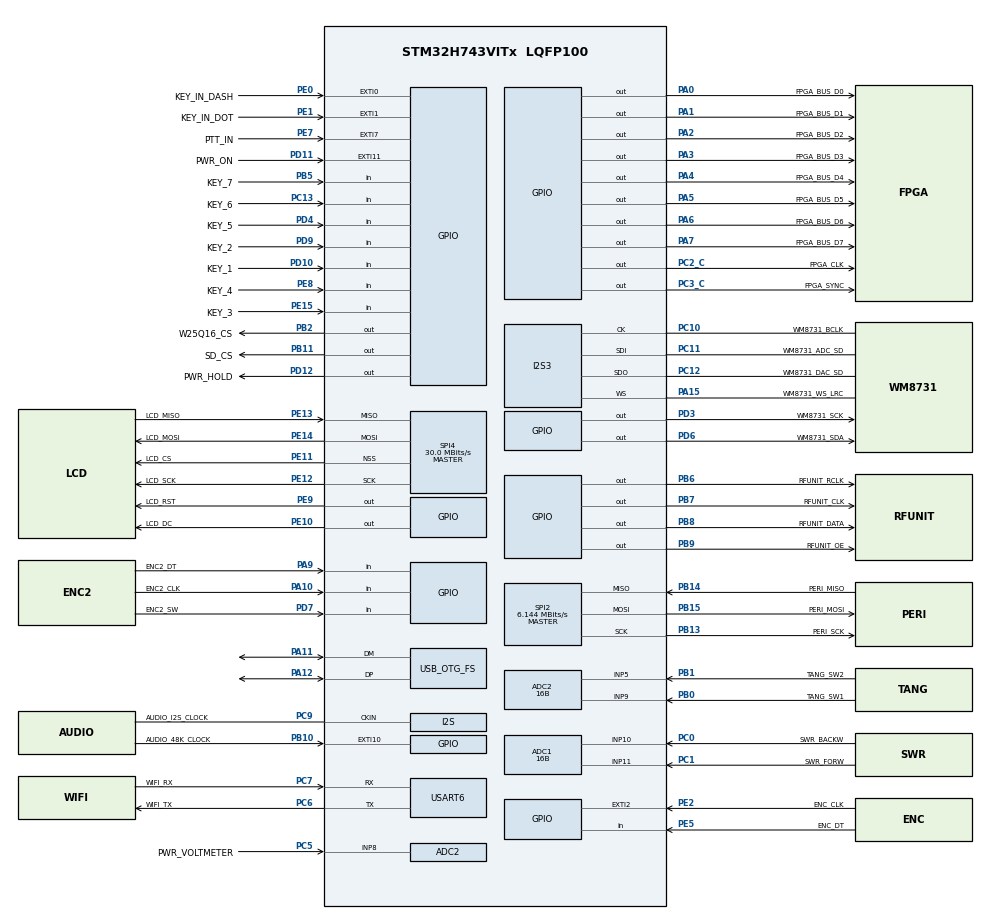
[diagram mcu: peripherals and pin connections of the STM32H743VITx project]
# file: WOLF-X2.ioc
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ADC1.ClockPrescaler=ADC_CLOCK_ASYNC_DIV256
ADC1.ContinuousConvMode=ENABLE
ADC1.ConversionDataManagement=ADC_CONVERSIONDATA_DR
ADC1.EOCSelection=ADC_EOC_SEQ_CONV
ADC1.EnableInjectedConversion=ENABLE
ADC1.EnableInjectedOversampling=DISABLE
ADC1.EnableRegularConversion=DISABLE
ADC1.ExternalTrigInjecConv=ADC_EXTERNALTRIGINJEC_T4_TRGO
ADC1.InjNumberOfConversion=2
ADC1.InjectedChannel-1\#ChannelInjectedConversion=ADC_CHANNEL_11
ADC1.InjectedChannel-2\#ChannelInjectedConversion=ADC_CHANNEL_10
ADC1.InjectedConvMode=None
ADC1.InjectedOffsetNumber-1\#ChannelInjectedConversion=ADC_OFFSET_NONE
ADC1.InjectedOffsetNumber-2\#ChannelInjectedConversion=ADC_OFFSET_NONE
ADC1.InjectedRank-1\#ChannelInjectedConversion=1
ADC1.InjectedRank-2\#ChannelInjectedConversion=2
ADC1.InjectedSamplingTime-1\#ChannelInjectedConversion=ADC_SAMPLETIME_1CYCLE_5
ADC1.InjectedSamplingTime-2\#ChannelInjectedConversion=ADC_SAMPLETIME_1CYCLE_5
ADC1.LowPowerAutoWait=DISABLE
ADC1.Overrun=ADC_OVR_DATA_OVERWRITTEN
ADC1.Resolution=ADC_RESOLUTION_16B
ADC1.injectedQueueMode=DISABLE
ADC1.master=1
ADC2.ClockPrescaler=ADC_CLOCK_ASYNC_DIV256
ADC2.ContinuousConvMode=ENABLE
ADC2.EOCSelection=ADC_EOC_SEQ_CONV
ADC2.EnableInjectedConversion=ENABLE
ADC2.EnableInjectedOversampling=DISABLE
ADC2.EnableRegularConversion=DISABLE
ADC2.ExternalTrigInjecConv=ADC_EXTERNALTRIGINJEC_T4_TRGO
ADC2.InjNumberOfConversion=4
ADC2.InjectedChannel-2\#ChannelInjectedConversion=ADC_CHANNEL_9
ADC2.InjectedChannel-3\#ChannelInjectedConversion=ADC_CHANNEL_5
ADC2.InjectedChannel-4\#ChannelInjectedConversion=ADC_CHANNEL_8
ADC2.InjectedChannel-5\#ChannelInjectedConversion=ADC_CHANNEL_5
ADC2.InjectedConvMode=None
ADC2.InjectedOffsetNumber-2\#ChannelInjectedConversion=ADC_OFFSET_NONE
ADC2.InjectedOffsetNumber-3\#ChannelInjectedConversion=ADC_OFFSET_NONE
ADC2.InjectedOffsetNumber-4\#ChannelInjectedConversion=ADC_OFFSET_NONE
ADC2.InjectedOffsetNumber-5\#ChannelInjectedConversion=ADC_OFFSET_NONE
ADC2.InjectedRank-2\#ChannelInjectedConversion=1
ADC2.InjectedRank-3\#ChannelInjectedConversion=2
ADC2.InjectedRank-4\#ChannelInjectedConversion=3
ADC2.InjectedRank-5\#ChannelInjectedConversion=4
ADC2.InjectedSamplingTime-2\#ChannelInjectedConversion=ADC_SAMPLETIME_32CYCLES_5
ADC2.InjectedSamplingTime-3\#ChannelInjectedConversion=ADC_SAMPLETIME_32CYCLES_5
ADC2.InjectedSamplingTime-4\#ChannelInjectedConversion=ADC_SAMPLETIME_32CYCLES_5
ADC2.InjectedSamplingTime-5\#ChannelInjectedConversion=ADC_SAMPLETIME_1CYCLE_5
ADC2.LowPowerAutoWait=DISABLE
ADC2.Overrun=ADC_OVR_DATA_OVERWRITTEN
ADC2.Resolution=ADC_RESOLUTION_16B
ADC3.ClockPrescaler=ADC_CLOCK_ASYNC_DIV256
ADC3.ContinuousConvMode=ENABLE
ADC3.EOCSelection=ADC_EOC_SEQ_CONV
ADC3.EnableInjectedConversion=ENABLE
ADC3.EnableInjectedOversampling=DISABLE
ADC3.EnableRegularConversion=DISABLE
ADC3.ExternalTrigInjecConv=ADC_EXTERNALTRIGINJEC_T4_TRGO
ADC3.InjNumberOfConversion=3
ADC3.InjectedChannel-2\#ChannelInjectedConversion=ADC_CHANNEL_TEMPSENSOR
ADC3.InjectedChannel-4\#ChannelInjectedConversion=ADC_CHANNEL_VREFINT
ADC3.InjectedChannel-5\#ChannelInjectedConversion=ADC_CHANNEL_VBAT
ADC3.InjectedConvMode=None
ADC3.InjectedOffsetNumber-2\#ChannelInjectedConversion=ADC_OFFSET_NONE
ADC3.InjectedOffsetNumber-4\#ChannelInjectedConversion=ADC_OFFSET_NONE
ADC3.InjectedOffsetNumber-5\#ChannelInjectedConversion=ADC_OFFSET_NONE
ADC3.InjectedRank-2\#ChannelInjectedConversion=1
ADC3.InjectedRank-4\#ChannelInjectedConversion=2
ADC3.InjectedRank-5\#ChannelInjectedConversion=3
ADC3.InjectedSamplingTime-2\#ChannelInjectedConversion=ADC_SAMPLETIME_810CYCLES_5
ADC3.InjectedSamplingTime-4\#ChannelInjectedConversion=ADC_SAMPLETIME_810CYCLES_5
ADC3.InjectedSamplingTime-5\#ChannelInjectedConversion=ADC_SAMPLETIME_810CYCLES_5
ADC3.LowPowerAutoWait=DISABLE
ADC3.Overrun=ADC_OVR_DATA_OVERWRITTEN
ADC3.injectedQueueMode=DISABLE
CORTEX_M7.AccessPermission-Cortex_Memory_Protection_Unit_Region0_Settings=MPU_REGION_FULL_ACCESS
CORTEX_M7.AccessPermission-Cortex_Memory_Protection_Unit_Region2_Settings=MPU_REGION_FULL_ACCESS
CORTEX_M7.BaseAddress-Cortex_Memory_Protection_Unit_Region0_Settings=0x60000000
CORTEX_M7.BaseAddress-Cortex_Memory_Protection_Unit_Region2_Settings=0x38800000
CORTEX_M7.CPU_DCache=Enabled
CORTEX_M7.CPU_ICache=Enabled
CORTEX_M7.DisableExec-Cortex_Memory_Protection_Unit_Region0_Settings=MPU_INSTRUCTION_ACCESS_ENABLE
CORTEX_M7.Enable-Cortex_Memory_Protection_Unit_Region0_Settings=MPU_REGION_ENABLE
CORTEX_M7.Enable-Cortex_Memory_Protection_Unit_Region2_Settings=MPU_REGION_ENABLE
CORTEX_M7.IsShareable-Cortex_Memory_Protection_Unit_Region0_Settings=MPU_ACCESS_SHAREABLE
CORTEX_M7.IsShareable-Cortex_Memory_Protection_Unit_Region2_Settings=MPU_ACCESS_SHAREABLE
CORTEX_M7.MPU_Control=MPU_PRIVILEGED_DEFAULT
CORTEX_M7.Size-Cortex_Memory_Protection_Unit_Region0_Settings=MPU_REGION_SIZE_1MB
CORTEX_M7.Size-Cortex_Memory_Protection_Unit_Region2_Settings=MPU_REGION_SIZE_4KB
CORTEX_M7.TypeExtField-Cortex_Memory_Protection_Unit_Region0_Settings=MPU_TEX_LEVEL0
Dma.Request0=SPI2_RX
Dma.Request1=SPI2_TX
Dma.Request2=SPI4_TX
Dma.Request3=USART6_RX
Dma.SPI2_RX.0.Direction=DMA_PERIPH_TO_MEMORY
Dma.SPI2_RX.0.EventEnable=DISABLE
Dma.SPI2_RX.0.FIFOMode=DMA_FIFOMODE_DISABLE
Dma.SPI2_RX.0.Instance=DMA1_Stream2
Dma.SPI2_RX.0.MemDataAlignment=DMA_MDATAALIGN_BYTE
Dma.SPI2_RX.0.MemInc=DMA_MINC_ENABLE
Dma.SPI2_RX.0.Mode=DMA_NORMAL
Dma.SPI2_RX.0.PeriphDataAlignment=DMA_PDATAALIGN_BYTE
Dma.SPI2_RX.0.PeriphInc=DMA_PINC_DISABLE
Dma.SPI2_RX.0.Polarity=HAL_DMAMUX_REQ_GEN_RISING
Dma.SPI2_RX.0.Priority=DMA_PRIORITY_MEDIUM
Dma.SPI2_RX.0.RequestNumber=1
Dma.SPI2_RX.0.SignalID=NONE
Dma.SPI2_RX.0.SyncEnable=DISABLE
Dma.SPI2_RX.0.SyncPolarity=HAL_DMAMUX_SYNC_NO_EVENT
Dma.SPI2_RX.0.SyncRequestNumber=1
Dma.SPI2_RX.0.SyncSignalID=NONE
Dma.SPI2_TX.1.Direction=DMA_MEMORY_TO_PERIPH
Dma.SPI2_TX.1.EventEnable=DISABLE
Dma.SPI2_TX.1.FIFOMode=DMA_FIFOMODE_DISABLE
Dma.SPI2_TX.1.Instance=DMA1_Stream3
Dma.SPI2_TX.1.MemDataAlignment=DMA_MDATAALIGN_BYTE
Dma.SPI2_TX.1.MemInc=DMA_MINC_ENABLE
Dma.SPI2_TX.1.Mode=DMA_NORMAL
Dma.SPI2_TX.1.PeriphDataAlignment=DMA_PDATAALIGN_BYTE
Dma.SPI2_TX.1.PeriphInc=DMA_PINC_DISABLE
Dma.SPI2_TX.1.Polarity=HAL_DMAMUX_REQ_GEN_RISING
Dma.SPI2_TX.1.Priority=DMA_PRIORITY_MEDIUM
Dma.SPI2_TX.1.RequestNumber=1
Dma.SPI2_TX.1.SignalID=NONE
Dma.SPI2_TX.1.SyncEnable=DISABLE
Dma.SPI2_TX.1.SyncPolarity=HAL_DMAMUX_SYNC_NO_EVENT
Dma.SPI2_TX.1.SyncRequestNumber=1
Dma.SPI2_TX.1.SyncSignalID=NONE
Dma.SPI4_TX.2.Direction=DMA_MEMORY_TO_PERIPH
Dma.SPI4_TX.2.EventEnable=DISABLE
Dma.SPI4_TX.2.FIFOMode=DMA_FIFOMODE_DISABLE
Dma.SPI4_TX.2.Instance=DMA2_Stream5
Dma.SPI4_TX.2.MemDataAlignment=DMA_MDATAALIGN_HALFWORD
Dma.SPI4_TX.2.MemInc=DMA_MINC_ENABLE
Dma.SPI4_TX.2.Mode=DMA_NORMAL
Dma.SPI4_TX.2.PeriphDataAlignment=DMA_PDATAALIGN_HALFWORD
Dma.SPI4_TX.2.PeriphInc=DMA_PINC_DISABLE
Dma.SPI4_TX.2.Polarity=HAL_DMAMUX_REQ_GEN_RISING
Dma.SPI4_TX.2.Priority=DMA_PRIORITY_LOW
Dma.SPI4_TX.2.RequestNumber=1
Dma.SPI4_TX.2.SignalID=NONE
Dma.SPI4_TX.2.SyncEnable=DISABLE
Dma.SPI4_TX.2.SyncPolarity=HAL_DMAMUX_SYNC_NO_EVENT
Dma.SPI4_TX.2.SyncRequestNumber=1
Dma.SPI4_TX.2.SyncSignalID=NONE
Dma.USART6_RX.3.Direction=DMA_PERIPH_TO_MEMORY
Dma.USART6_RX.3.EventEnable=DISABLE
Dma.USART6_RX.3.FIFOMode=DMA_FIFOMODE_DISABLE
Dma.USART6_RX.3.Instance=DMA1_Stream1
Dma.USART6_RX.3.MemDataAlignment=DMA_MDATAALIGN_BYTE
Dma.USART6_RX.3.MemInc=DMA_MINC_ENABLE
Dma.USART6_RX.3.Mode=DMA_CIRCULAR
Dma.USART6_RX.3.PeriphDataAlignment=DMA_PDATAALIGN_BYTE
Dma.USART6_RX.3.PeriphInc=DMA_PINC_DISABLE
Dma.USART6_RX.3.Polarity=HAL_DMAMUX_REQ_GEN_RISING
Dma.USART6_RX.3.Priority=DMA_PRIORITY_HIGH
Dma.USART6_RX.3.RequestNumber=1
Dma.USART6_RX.3.SignalID=NONE
Dma.USART6_RX.3.SyncEnable=DISABLE
Dma.USART6_RX.3.SyncPolarity=HAL_DMAMUX_SYNC_NO_EVENT
Dma.USART6_RX.3.SyncRequestNumber=1
Dma.USART6_RX.3.SyncSignalID=NONE
FATFS._MAX_SS=4096
FATFS._USE_FASTSEEK=0
FATFS._USE_LFN=1
FATFS._USE_MKFS=1
I2S3.AudioFreq=I2S_AUDIOFREQ_48K
I2S3.DataFormat=I2S_DATAFORMAT_32B
I2S3.ErrorAudioFreq=0.0 %
I2S3.FullDuplexMode=I2S_MODE_MASTER_FD
I2S3.Instance=SPI$Index
I2S3.MasterKeepIOState=I2S_MASTER_KEEP_IO_STATE_ENABLE
I2S3.RealAudioFreq=48.0 KHz
I2S3.VirtualMode=I2S_MODE_MASTER
IWDG1.Reload=1500
IWDG1.Window=1500
Mcu.Family=STM32H7
Mcu.Name=STM32H743VITx
Mcu.Package=LQFP100
Mdma.MDMA_Channel0.Request0=SW
Mdma.MDMA_Channel0.RequestsNb=1
Mdma.MDMA_Channel0.SW.0.BlockCount=0
Mdma.MDMA_Channel0.SW.0.BlockDataLength=0
Mdma.MDMA_Channel0.SW.0.BufferTransferLength=32
Mdma.MDMA_Channel0.SW.0.CircularMode=MDMA_LINEAR_LIST
Mdma.MDMA_Channel0.SW.0.DataAlignment=MDMA_DATAALIGN_PACKENABLE
Mdma.MDMA_Channel0.SW.0.DestBlockAddressOffset=0
Mdma.MDMA_Channel0.SW.0.DestBurst=MDMA_DEST_BURST_SINGLE
Mdma.MDMA_Channel0.SW.0.DestDataSize=MDMA_DEST_DATASIZE_WORD
Mdma.MDMA_Channel0.SW.0.DestinationInc=MDMA_DEST_INC_WORD
Mdma.MDMA_Channel0.SW.0.DstAddress=0
Mdma.MDMA_Channel0.SW.0.Endianness=MDMA_LITTLE_ENDIANNESS_PRESERVE
Mdma.MDMA_Channel0.SW.0.Instance=MDMA_Channel0
Mdma.MDMA_Channel0.SW.0.MaskAddress=0
Mdma.MDMA_Channel0.SW.0.MaskData=0
Mdma.MDMA_Channel0.SW.0.Priority=MDMA_PRIORITY_MEDIUM
Mdma.MDMA_Channel0.SW.0.Rank=First
Mdma.MDMA_Channel0.SW.0.SourceBlockAddressOffset=0
Mdma.MDMA_Channel0.SW.0.SourceBurst=MDMA_SOURCE_BURST_SINGLE
Mdma.MDMA_Channel0.SW.0.SourceDataSize=MDMA_SRC_DATASIZE_WORD
Mdma.MDMA_Channel0.SW.0.SourceInc=MDMA_SRC_INC_WORD
Mdma.MDMA_Channel0.SW.0.SrcAddress=0
Mdma.MDMA_Channel0.SW.0.TransferTriggerMode=MDMA_FULL_TRANSFER
Mdma.MDMA_Channel1.Request0=SW
Mdma.MDMA_Channel1.RequestsNb=1
Mdma.MDMA_Channel1.SW.0.BlockCount=0
Mdma.MDMA_Channel1.SW.0.BlockDataLength=0
Mdma.MDMA_Channel1.SW.0.BufferTransferLength=32
Mdma.MDMA_Channel1.SW.0.CircularMode=MDMA_LINEAR_LIST
Mdma.MDMA_Channel1.SW.0.DataAlignment=MDMA_DATAALIGN_PACKENABLE
Mdma.MDMA_Channel1.SW.0.DestBlockAddressOffset=0
Mdma.MDMA_Channel1.SW.0.DestBurst=MDMA_DEST_BURST_SINGLE
Mdma.MDMA_Channel1.SW.0.DestDataSize=MDMA_DEST_DATASIZE_WORD
Mdma.MDMA_Channel1.SW.0.DestinationInc=MDMA_DEST_INC_WORD
Mdma.MDMA_Channel1.SW.0.DstAddress=0
Mdma.MDMA_Channel1.SW.0.Endianness=MDMA_LITTLE_ENDIANNESS_PRESERVE
Mdma.MDMA_Channel1.SW.0.Instance=MDMA_Channel1
Mdma.MDMA_Channel1.SW.0.MaskAddress=0
Mdma.MDMA_Channel1.SW.0.MaskData=0
Mdma.MDMA_Channel1.SW.0.Priority=MDMA_PRIORITY_MEDIUM
Mdma.MDMA_Channel1.SW.0.Rank=First
Mdma.MDMA_Channel1.SW.0.SourceBlockAddressOffset=0
Mdma.MDMA_Channel1.SW.0.SourceBurst=MDMA_SOURCE_BURST_SINGLE
Mdma.MDMA_Channel1.SW.0.SourceDataSize=MDMA_SRC_DATASIZE_WORD
Mdma.MDMA_Channel1.SW.0.SourceInc=MDMA_SRC_INC_WORD
Mdma.MDMA_Channel1.SW.0.SrcAddress=0
Mdma.MDMA_Channel1.SW.0.TransferTriggerMode=MDMA_FULL_TRANSFER
Mdma.MDMA_Channel2.Request0=SW
Mdma.MDMA_Channel2.RequestsNb=1
Mdma.MDMA_Channel2.SW.0.BlockCount=0
Mdma.MDMA_Channel2.SW.0.BlockDataLength=0
Mdma.MDMA_Channel2.SW.0.BufferTransferLength=32
Mdma.MDMA_Channel2.SW.0.CircularMode=MDMA_LINEAR_LIST
Mdma.MDMA_Channel2.SW.0.DataAlignment=MDMA_DATAALIGN_PACKENABLE
Mdma.MDMA_Channel2.SW.0.DestBlockAddressOffset=0
Mdma.MDMA_Channel2.SW.0.DestBurst=MDMA_DEST_BURST_SINGLE
Mdma.MDMA_Channel2.SW.0.DestDataSize=MDMA_DEST_DATASIZE_WORD
Mdma.MDMA_Channel2.SW.0.DestinationInc=MDMA_DEST_INC_WORD
Mdma.MDMA_Channel2.SW.0.DstAddress=0
Mdma.MDMA_Channel2.SW.0.Endianness=MDMA_LITTLE_ENDIANNESS_PRESERVE
Mdma.MDMA_Channel2.SW.0.Instance=MDMA_Channel2
Mdma.MDMA_Channel2.SW.0.MaskAddress=0
Mdma.MDMA_Channel2.SW.0.MaskData=0
Mdma.MDMA_Channel2.SW.0.Priority=MDMA_PRIORITY_MEDIUM
Mdma.MDMA_Channel2.SW.0.Rank=First
Mdma.MDMA_Channel2.SW.0.SourceBlockAddressOffset=0
Mdma.MDMA_Channel2.SW.0.SourceBurst=MDMA_SOURCE_BURST_SINGLE
Mdma.MDMA_Channel2.SW.0.SourceDataSize=MDMA_SRC_DATASIZE_WORD
Mdma.MDMA_Channel2.SW.0.SourceInc=MDMA_SRC_INC_WORD
Mdma.MDMA_Channel2.SW.0.SrcAddress=0
Mdma.MDMA_Channel2.SW.0.TransferTriggerMode=MDMA_FULL_TRANSFER
Mdma.MDMA_Channel3.Request0=SW
Mdma.MDMA_Channel3.RequestsNb=1
Mdma.MDMA_Channel3.SW.0.BlockCount=0
Mdma.MDMA_Channel3.SW.0.BlockDataLength=0
Mdma.MDMA_Channel3.SW.0.BufferTransferLength=32
Mdma.MDMA_Channel3.SW.0.CircularMode=MDMA_LINEAR_LIST
Mdma.MDMA_Channel3.SW.0.DataAlignment=MDMA_DATAALIGN_PACKENABLE
Mdma.MDMA_Channel3.SW.0.DestBlockAddressOffset=0
Mdma.MDMA_Channel3.SW.0.DestBurst=MDMA_DEST_BURST_SINGLE
Mdma.MDMA_Channel3.SW.0.DestDataSize=MDMA_DEST_DATASIZE_BYTE
Mdma.MDMA_Channel3.SW.0.DestinationInc=MDMA_DEST_DEC_BYTE
Mdma.MDMA_Channel3.SW.0.DstAddress=0
Mdma.MDMA_Channel3.SW.0.Endianness=MDMA_LITTLE_ENDIANNESS_PRESERVE
Mdma.MDMA_Channel3.SW.0.Instance=MDMA_Channel3
Mdma.MDMA_Channel3.SW.0.MaskAddress=0
Mdma.MDMA_Channel3.SW.0.MaskData=0
Mdma.MDMA_Channel3.SW.0.Priority=MDMA_PRIORITY_LOW
Mdma.MDMA_Channel3.SW.0.Rank=First
Mdma.MDMA_Channel3.SW.0.SourceBlockAddressOffset=0
Mdma.MDMA_Channel3.SW.0.SourceBurst=MDMA_SOURCE_BURST_SINGLE
Mdma.MDMA_Channel3.SW.0.SourceDataSize=MDMA_SRC_DATASIZE_BYTE
Mdma.MDMA_Channel3.SW.0.SourceInc=MDMA_SRC_DEC_BYTE
Mdma.MDMA_Channel3.SW.0.SrcAddress=0
Mdma.MDMA_Channel3.SW.0.TransferTriggerMode=MDMA_FULL_TRANSFER
Mdma.MDMA_Channel4.Request0=SW
Mdma.MDMA_Channel4.RequestsNb=1
Mdma.MDMA_Channel4.SW.0.BlockCount=0
Mdma.MDMA_Channel4.SW.0.BlockDataLength=0
Mdma.MDMA_Channel4.SW.0.BufferTransferLength=32
Mdma.MDMA_Channel4.SW.0.CircularMode=MDMA_LINEAR_LIST
Mdma.MDMA_Channel4.SW.0.DataAlignment=MDMA_DATAALIGN_PACKENABLE
Mdma.MDMA_Channel4.SW.0.DestBlockAddressOffset=0
Mdma.MDMA_Channel4.SW.0.DestBurst=MDMA_DEST_BURST_SINGLE
Mdma.MDMA_Channel4.SW.0.DestDataSize=MDMA_DEST_DATASIZE_WORD
Mdma.MDMA_Channel4.SW.0.DestinationInc=MDMA_DEST_INC_WORD
Mdma.MDMA_Channel4.SW.0.DstAddress=0
Mdma.MDMA_Channel4.SW.0.Endianness=MDMA_LITTLE_ENDIANNESS_PRESERVE
Mdma.MDMA_Channel4.SW.0.Instance=MDMA_Channel4
Mdma.MDMA_Channel4.SW.0.MaskAddress=0
Mdma.MDMA_Channel4.SW.0.MaskData=0
Mdma.MDMA_Channel4.SW.0.Priority=MDMA_PRIORITY_MEDIUM
Mdma.MDMA_Channel4.SW.0.Rank=First
Mdma.MDMA_Channel4.SW.0.SourceBlockAddressOffset=0
Mdma.MDMA_Channel4.SW.0.SourceBurst=MDMA_SOURCE_BURST_SINGLE
Mdma.MDMA_Channel4.SW.0.SourceDataSize=MDMA_SRC_DATASIZE_WORD
Mdma.MDMA_Channel4.SW.0.SourceInc=MDMA_SRC_INC_DISABLE
Mdma.MDMA_Channel4.SW.0.SrcAddress=0
Mdma.MDMA_Channel4.SW.0.TransferTriggerMode=MDMA_FULL_TRANSFER
Mdma.RequestSet0=MDMA_Channel0
Mdma.RequestSet1=MDMA_Channel1
Mdma.RequestSet2=MDMA_Channel2
Mdma.RequestSet3=MDMA_Channel3
Mdma.RequestSet4=MDMA_Channel4
Mdma.RequestSetsNb=5
NVIC.DMA1_Stream1_IRQn=true\:1\:0\:true\:false\:true\:true\:true\:true
NVIC.DMA1_Stream2_IRQn=true\:0\:0\:true\:false\:true\:false\:true\:true
NVIC.DMA1_Stream3_IRQn=true\:0\:0\:true\:false\:true\:false\:true\:true
NVIC.DMA2_Stream5_IRQn=true\:0\:0\:false\:false\:true\:true\:true\:true
NVIC.EXTI0_IRQn=true\:6\:0\:true\:false\:true\:true\:true\:true
NVIC.EXTI15_10_IRQn=true\:3\:0\:true\:false\:true\:true\:true\:true
NVIC.EXTI1_IRQn=true\:6\:0\:true\:false\:true\:true\:true\:true
NVIC.EXTI2_IRQn=true\:2\:0\:true\:false\:true\:true\:true\:true
NVIC.EXTI9_5_IRQn=true\:6\:0\:true\:false\:true\:true\:true\:true
NVIC.OTG_FS_IRQn=true\:1\:0\:true\:false\:true\:true\:true\:true
NVIC.PriorityGroup=NVIC_PRIORITYGROUP_4
NVIC.SPI2_IRQn=true\:0\:0\:false\:false\:true\:false\:true\:true
NVIC.SPI4_IRQn=true\:0\:0\:false\:false\:true\:false\:true\:true
NVIC.TIM15_IRQn=true\:11\:0\:true\:false\:true\:true\:true\:true
NVIC.TIM16_IRQn=true\:2\:0\:true\:false\:true\:true\:true\:true
NVIC.TIM17_IRQn=true\:4\:0\:true\:false\:true\:true\:true\:true
NVIC.TIM2_IRQn=true\:1\:0\:true\:false\:true\:true\:true\:true
NVIC.TIM3_IRQn=true\:12\:0\:true\:false\:true\:true\:true\:true
NVIC.TIM4_IRQn=true\:9\:0\:true\:false\:true\:true\:true\:true
NVIC.TIM5_IRQn=true\:5\:0\:true\:false\:true\:true\:true\:true
NVIC.TIM6_DAC_IRQn=true\:8\:0\:true\:false\:true\:true\:true\:true
NVIC.TIM7_IRQn=true\:10\:0\:true\:false\:true\:true\:true\:true
NVIC.USART6_IRQn=true\:1\:0\:true\:false\:true\:true\:true\:true
PA0.GPIO_Label=FPGA_BUS_D0
PA0.GPIO_PuPd=GPIO_PULLUP
PA0.GPIO_Speed=GPIO_SPEED_FREQ_LOW
PA0.Signal=GPIO_Output
PA1.GPIO_Label=FPGA_BUS_D1
PA1.GPIO_PuPd=GPIO_PULLUP
PA1.GPIO_Speed=GPIO_SPEED_FREQ_LOW
PA1.Signal=GPIO_Output
PA10.GPIO_Label=ENC2_CLK
PA10.GPIO_PuPd=GPIO_PULLUP
PA10.Signal=GPIO_Input
PA11.GPIO_PuPd=GPIO_NOPULL
PA11.GPIO_Speed=GPIO_SPEED_FREQ_LOW
PA11.Mode=Device_Only
PA11.Signal=USB_OTG_FS_DM
PA12.GPIO_PuPd=GPIO_NOPULL
PA12.GPIO_Speed=GPIO_SPEED_FREQ_LOW
PA12.Mode=Device_Only
PA12.Signal=USB_OTG_FS_DP
PA13\ (JTMS/SWDIO).Mode=Trace_Asynchronous_SW
PA13\ (JTMS/SWDIO).Signal=DEBUG_JTMS-SWDIO
PA14\ (JTCK/SWCLK).Mode=Trace_Asynchronous_SW
PA14\ (JTCK/SWCLK).Signal=DEBUG_JTCK-SWCLK
PA15\ (JTDI).GPIO_Label=WM8731_WS_LRC
PA15\ (JTDI).GPIO_Speed=GPIO_SPEED_FREQ_LOW
PA15\ (JTDI).Mode=Full_Duplex_Master
PA15\ (JTDI).Signal=I2S3_WS
PA2.GPIO_Label=FPGA_BUS_D2
PA2.GPIO_PuPd=GPIO_PULLUP
PA2.GPIO_Speed=GPIO_SPEED_FREQ_LOW
PA2.Signal=GPIO_Output
PA3.GPIO_Label=FPGA_BUS_D3
PA3.GPIO_PuPd=GPIO_PULLUP
PA3.GPIO_Speed=GPIO_SPEED_FREQ_LOW
PA3.Signal=GPIO_Output
PA4.GPIO_Label=FPGA_BUS_D4
PA4.GPIO_PuPd=GPIO_PULLUP
PA4.GPIO_Speed=GPIO_SPEED_FREQ_LOW
PA4.Signal=GPIO_Output
PA5.GPIO_Label=FPGA_BUS_D5
PA5.GPIO_PuPd=GPIO_PULLUP
PA5.GPIO_Speed=GPIO_SPEED_FREQ_LOW
PA5.Signal=GPIO_Output
PA6.GPIO_Label=FPGA_BUS_D6
PA6.GPIO_PuPd=GPIO_PULLUP
PA6.GPIO_Speed=GPIO_SPEED_FREQ_LOW
PA6.Signal=GPIO_Output
PA7.GPIO_Label=FPGA_BUS_D7
PA7.GPIO_PuPd=GPIO_PULLUP
PA7.GPIO_Speed=GPIO_SPEED_FREQ_LOW
PA7.Signal=GPIO_Output
PA9.GPIO_Label=ENC2_DT
PA9.GPIO_PuPd=GPIO_PULLUP
PA9.Signal=GPIO_Input
PB0.GPIO_Label=TANG_SW1
PB0.Signal=ADCx_INP9
PB1.GPIO_Label=TANG_SW2
PB1.Signal=ADCx_INP5
PB10.GPIO_Label=AUDIO_48K_CLOCK
PB10.GPIO_PuPd=GPIO_PULLUP
PB10.Signal=GPXTI10
PB11.GPIO_Label=SD_CS
PB11.GPIO_PuPd=GPIO_PULLUP
PB11.PinState=GPIO_PIN_SET
PB11.Signal=GPIO_Output
PB13.GPIO_Label=PERI_SCK
PB13.GPIO_PuPd=GPIO_PULLUP
PB13.GPIO_Speed=GPIO_SPEED_FREQ_LOW
PB13.Mode=Full_Duplex_Master
PB13.Signal=SPI2_SCK
PB14.GPIO_Label=PERI_MISO
PB14.GPIO_PuPd=GPIO_PULLUP
PB14.GPIO_Speed=GPIO_SPEED_FREQ_LOW
PB14.Mode=Full_Duplex_Master
PB14.Signal=SPI2_MISO
PB15.GPIO_Label=PERI_MOSI
PB15.GPIO_PuPd=GPIO_PULLUP
PB15.GPIO_Speed=GPIO_SPEED_FREQ_LOW
PB15.Mode=Full_Duplex_Master
PB15.Signal=SPI2_MOSI
PB2.GPIO_Label=W25Q16_CS
PB2.GPIO_PuPd=GPIO_PULLUP
PB2.PinState=GPIO_PIN_SET
PB2.Signal=GPIO_Output
PB3\ (JTDO/TRACESWO).Mode=Trace_Asynchronous_SW
PB3\ (JTDO/TRACESWO).Signal=DEBUG_JTDO-SWO
PB5.GPIO_Label=KEY_7
PB5.GPIO_PuPd=GPIO_PULLUP
PB5.Signal=GPIO_Input
PB6.GPIO_Label=RFUNIT_RCLK
PB6.GPIO_PuPd=GPIO_PULLUP
PB6.GPIO_Speed=GPIO_SPEED_FREQ_LOW
PB6.Signal=GPIO_Output
PB7.GPIO_Label=RFUNIT_CLK
PB7.GPIO_PuPd=GPIO_PULLUP
PB7.GPIO_Speed=GPIO_SPEED_FREQ_LOW
PB7.Signal=GPIO_Output
PB8.GPIO_Label=RFUNIT_DATA
PB8.GPIO_PuPd=GPIO_PULLUP
PB8.GPIO_Speed=GPIO_SPEED_FREQ_LOW
PB8.Signal=GPIO_Output
PB9.GPIO_Label=RFUNIT_OE
PB9.GPIO_PuPd=GPIO_PULLUP
PB9.GPIO_Speed=GPIO_SPEED_FREQ_LOW
PB9.PinState=GPIO_PIN_SET
PB9.Signal=GPIO_Output
PC0.GPIO_Label=SWR_BACKW
PC0.Signal=ADCx_INP10
PC1.GPIO_Label=SWR_FORW
PC1.Signal=ADCx_INP11
PC10.GPIO_Label=WM8731_BCLK
PC10.GPIO_Speed=GPIO_SPEED_FREQ_LOW
PC10.Mode=Full_Duplex_Master
PC10.Signal=I2S3_CK
PC11.GPIO_Label=WM8731_ADC_SD
PC11.GPIO_Speed=GPIO_SPEED_FREQ_LOW
PC11.Mode=Full_Duplex_Master
PC11.Signal=I2S3_SDI
PC12.GPIO_Label=WM8731_DAC_SD
PC12.GPIO_Speed=GPIO_SPEED_FREQ_LOW
PC12.Mode=Full_Duplex_Master
PC12.Signal=I2S3_SDO
PC13.GPIO_Label=KEY_6
PC13.GPIO_PuPd=GPIO_PULLUP
PC13.Signal=GPIO_Input
PC14-OSC32_IN\ (OSC32_IN).Mode=LSE-External-Oscillator
PC14-OSC32_IN\ (OSC32_IN).Signal=RCC_OSC32_IN
PC15-OSC32_OUT\ (OSC32_OUT).Mode=LSE-External-Oscillator
PC15-OSC32_OUT\ (OSC32_OUT).Signal=RCC_OSC32_OUT
PC2_C.GPIO_Label=FPGA_CLK
PC2_C.GPIO_PuPd=GPIO_PULLUP
PC2_C.GPIO_Speed=GPIO_SPEED_FREQ_LOW
PC2_C.Signal=GPIO_Output
PC3_C.GPIO_Label=FPGA_SYNC
PC3_C.GPIO_PuPd=GPIO_PULLUP
PC3_C.GPIO_Speed=GPIO_SPEED_FREQ_LOW
PC3_C.Signal=GPIO_Output
PC5.GPIO_Label=PWR_VOLTMETER
PC5.Signal=ADCx_INP8
PC6.GPIO_Label=WIFI_TX
PC6.Mode=Asynchronous
PC6.Signal=USART6_TX
PC7.GPIO_Label=WIFI_RX
PC7.Mode=Asynchronous
PC7.Signal=USART6_RX
PC9.GPIO_Label=AUDIO_I2S_CLOCK
PC9.GPIO_PuPd=GPIO_PULLDOWN
PC9.GPIO_Speed=GPIO_SPEED_FREQ_LOW
PC9.Mode=Audio_ClockIn
PC9.Signal=I2S_CKIN
PD10.GPIO_Label=KEY_1
PD10.GPIO_PuPd=GPIO_PULLUP
PD10.Signal=GPIO_Input
PD11.GPIO_Label=PWR_ON
PD11.GPIO_ModeDefaultEXTI=GPIO_MODE_IT_FALLING
PD11.GPIO_PuPd=GPIO_PULLUP
PD11.Signal=GPXTI11
PD12.GPIO_Label=PWR_HOLD
PD12.GPIO_PuPd=GPIO_PULLUP
PD12.PinState=GPIO_PIN_SET
PD12.Signal=GPIO_Output
PD3.GPIO_Label=WM8731_SCK
PD3.GPIO_PuPd=GPIO_PULLUP
PD3.Signal=GPIO_Output
PD4.GPIO_Label=KEY_5
PD4.GPIO_PuPd=GPIO_PULLUP
PD4.Signal=GPIO_Input
PD6.GPIO_Label=WM8731_SDA
PD6.GPIO_PuPd=GPIO_PULLUP
PD6.Signal=GPIO_Output
PD7.GPIO_Label=ENC2_SW
PD7.GPIO_PuPd=GPIO_PULLUP
PD7.Signal=GPIO_Input
PD9.GPIO_Label=KEY_2
PD9.GPIO_PuPd=GPIO_PULLUP
PD9.Signal=GPIO_Input
PE0.GPIO_Label=KEY_IN_DASH
PE0.GPIO_ModeDefaultEXTI=GPIO_MODE_IT_RISING_FALLING
PE0.GPIO_PuPd=GPIO_PULLUP
PE0.Signal=GPXTI0
PE1.GPIO_Label=KEY_IN_DOT
PE1.GPIO_ModeDefaultEXTI=GPIO_MODE_IT_RISING_FALLING
PE1.GPIO_PuPd=GPIO_PULLUP
PE1.Signal=GPXTI1
PE10.GPIO_Label=LCD_DC
PE10.GPIO_PuPd=GPIO_PULLUP
PE10.Signal=GPIO_Output
PE11.GPIO_Label=LCD_CS
PE11.GPIO_PuPd=GPIO_PULLUP
PE11.GPIO_Speed=GPIO_SPEED_FREQ_LOW
PE11.Mode=NSS_Signal_Hard_Output
PE11.Signal=SPI4_NSS
PE12.GPIO_Label=LCD_SCK
PE12.GPIO_PuPd=GPIO_PULLUP
PE12.GPIO_Speed=GPIO_SPEED_FREQ_LOW
PE12.Mode=Full_Duplex_Master
PE12.Signal=SPI4_SCK
PE13.GPIO_Label=LCD_MISO
PE13.Mode=Full_Duplex_Master
PE13.Signal=SPI4_MISO
PE14.GPIO_Label=LCD_MOSI
PE14.GPIO_PuPd=GPIO_PULLUP
PE14.GPIO_Speed=GPIO_SPEED_FREQ_LOW
PE14.Mode=Full_Duplex_Master
PE14.Signal=SPI4_MOSI
PE15.GPIO_Label=KEY_3
PE15.GPIO_PuPd=GPIO_PULLUP
PE15.Signal=GPIO_Input
PE2.GPIO_Label=ENC_CLK
PE2.GPIO_ModeDefaultEXTI=GPIO_MODE_IT_RISING_FALLING
PE2.GPIO_PuPd=GPIO_PULLUP
PE2.Signal=GPXTI2
PE5.GPIO_Label=ENC_DT
PE5.GPIO_PuPd=GPIO_PULLUP
PE5.Signal=GPIO_Input
PE7.GPIO_Label=PTT_IN
PE7.GPIO_ModeDefaultEXTI=GPIO_MODE_IT_RISING_FALLING
PE7.GPIO_PuPd=GPIO_PULLUP
PE7.Signal=GPXTI7
PE8.GPIO_Label=KEY_4
PE8.GPIO_PuPd=GPIO_PULLUP
PE8.Signal=GPIO_Input
PE9.GPIO_Label=LCD_RST
PE9.GPIO_PuPd=GPIO_PULLUP
PE9.Signal=GPIO_Output
PH0-OSC_IN\ (PH0).Mode=HSE-External-Oscillator
PH0-OSC_IN\ (PH0).Signal=RCC_OSC_IN
PH1-OSC_OUT\ (PH1).Mode=HSE-External-Oscillator
PH1-OSC_OUT\ (PH1).Signal=RCC_OSC_OUT
ProjectManager.HeapSize=0x000
ProjectManager.StackSize=0x2000
ProjectManager.TargetToolchain=MDK-ARM V5.32
RCC.ADCCLockSelection=RCC_ADCCLKSOURCE_CLKP
RCC.ADCFreq_Value=64000000
RCC.APB1Freq_Value=120000000
RCC.APB2Freq_Value=120000000
RCC.APB3Freq_Value=120000000
RCC.APB4Freq_Value=120000000
RCC.CortexFreq_Value=480000000
RCC.D1PPRE=RCC_APB3_DIV2
RCC.D2PPRE1=RCC_APB1_DIV2
RCC.D2PPRE2=RCC_APB2_DIV2
RCC.D3PPRE=RCC_APB4_DIV2
RCC.DIVM1=2
RCC.DIVM2=8
RCC.DIVM3=4
RCC.DIVN1=240
RCC.DIVN2=336
RCC.DIVN3=96
RCC.DIVQ3=4
RCC.EXTERNAL_CLOCK_VALUE=12288000
RCC.HCLKFreq_Value=240000000
RCC.HPRE=RCC_HCLK_DIV2
RCC.HSE_VALUE=8000000
RCC.HSICalibrationValue=32
RCC.LSE_Drive_Capability=RCC_LSEDRIVE_HIGH
RCC.LSE_Timout=5000
RCC.PLLSourceVirtual=RCC_PLLSOURCE_HSE
RCC.PWR_Regulator_Voltage_Scale=PWR_REGULATOR_VOLTAGE_SCALE0
RCC.RCC_RTC_Clock_Source_FROM_HSE=RCC_RTCCLKSOURCE_HSE_DIV8
RCC.RTCClockSelection=RCC_RTCCLKSOURCE_LSE
RCC.SPI123CLockSelection=RCC_SPI123CLKSOURCE_PIN
RCC.SYSCLKFreq_VALUE=480000000
RCC.SYSCLKSource=RCC_SYSCLKSOURCE_PLLCLK
RCC.SupplySource=PWR_LDO_SUPPLY
RCC.USBCLockSelection=RCC_USBCLKSOURCE_PLL3
RCC.USBFreq_Value=48000000
RTC.AsynchPrediv=127
RTC.SynchPrediv=255
SH.ADCx_INP10.0=ADC1_INP10,IN10-Single-Ended
SH.ADCx_INP11.0=ADC1_INP11,IN11-Single-Ended
SH.ADCx_INP11.1=ADC2_INP11
SH.ADCx_INP5.0=ADC1_INP5
SH.ADCx_INP5.1=ADC2_INP5,IN5-Single-Ended
SH.ADCx_INP8.0=ADC1_INP8
SH.ADCx_INP8.1=ADC2_INP8,IN8-Single-Ended
SH.ADCx_INP9.0=ADC1_INP9
SH.ADCx_INP9.1=ADC2_INP9,IN9-Single-Ended
SPI2.BaudRatePrescaler=SPI_BAUDRATEPRESCALER_2
SPI2.CalculateBaudRate=6.144 MBits/s
SPI2.DataSize=SPI_DATASIZE_8BIT
SPI2.Direction=SPI_DIRECTION_2LINES
SPI2.Mode=SPI_MODE_MASTER
SPI2.NSSPMode=SPI_NSS_PULSE_DISABLE
SPI2.VirtualType=VM_MASTER
SPI4.BaudRatePrescaler=SPI_BAUDRATEPRESCALER_4
SPI4.CalculateBaudRate=30.0 MBits/s
SPI4.DataSize=SPI_DATASIZE_8BIT
SPI4.Direction=SPI_DIRECTION_2LINES
SPI4.Mode=SPI_MODE_MASTER
SPI4.VirtualNSS=VM_NSSHARD
SPI4.VirtualType=VM_MASTER
TIM15.Period=199
TIM15.Prescaler=1199
TIM15.TIM_MasterOutputTrigger=TIM_TRGO_UPDATE
TIM16.Period=199
TIM16.Prescaler=1199
TIM17.Period=99
TIM17.Prescaler=119
TIM2.Period=10025
TIM2.Prescaler=16341
TIM2.TIM_MasterOutputTrigger=TIM_TRGO_UPDATE
TIM3.Period=199
TIM3.Prescaler=1199
TIM3.TIM_MasterOutputTrigger=TIM_TRGO_UPDATE
TIM4.Period=199
TIM4.Prescaler=1199
TIM4.TIM_MasterOutputTrigger=TIM_TRGO_UPDATE
TIM5.AutoReloadPreload=TIM_AUTORELOAD_PRELOAD_DISABLE
TIM5.Period=99
TIM5.Prescaler=119
TIM5.TIM_MasterOutputTrigger=TIM_TRGO_UPDATE
TIM6.Period=199
TIM6.Prescaler=11999
TIM6.TIM_MasterOutputTrigger=TIM_TRGO_UPDATE
TIM7.Period=199
TIM7.Prescaler=1199
TIM7.TIM_MasterOutputTrigger=TIM_TRGO_UPDATE
USART6.VirtualMode=VM_ASYNC
USB_OTG_FS.Sof_enable=ENABLE
USB_OTG_FS.VirtualMode=Device_Only
VP_ADC3_TempSens_Input.Mode=IN-TempSens
VP_ADC3_Vbat_Input.Mode=IN-Vbat
VP_ADC3_Vref_Input.Mode=IN-Vrefint
VP_CRC_VS_CRC.Mode=CRC_Activate
VP_FATFS_VS_Generic.Mode=User_defined
VP_IWDG1_VS_IWDG.Mode=IWDG_Activate
VP_RTC_VS_RTC_Activate.Mode=RTC_Enabled
VP_TIM15_VS_ClockSourceINT.Mode=Internal
VP_TIM16_VS_ClockSourceINT.Mode=Enable_Timer
VP_TIM17_VS_ClockSourceINT.Mode=Enable_Timer
VP_TIM2_VS_ClockSourceINT.Mode=Internal
VP_TIM3_VS_ClockSourceINT.Mode=Internal
VP_TIM4_VS_ClockSourceINT.Mode=Internal
VP_TIM5_VS_ClockSourceINT.Mode=Internal
VP_TIM6_VS_ClockSourceINT.Mode=Enable_Timer
VP_TIM7_VS_ClockSourceINT.Mode=Enable_Timer
board=custom

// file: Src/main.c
/* USER CODE BEGIN Header */
/**
  ******************************************************************************
  * @file           : main.c
  * @brief          : Main program body
  ******************************************************************************
  * @attention
  *
  * <h2><center>&copy; Copyright (c) 2020 STMicroelectronics.
  * All rights reserved.</center></h2>
  *
  * This software component is licensed by ST under BSD 3-Clause license,
  * the "License"; You may not use this file except in compliance with the
  * License. You may obtain a copy of the License at:
  *                        opensource.org/licenses/BSD-3-Clause
  *
  ******************************************************************************
  */
/* USER CODE END Header */
#include "main.h"
#include "fatfs.h"

/* USER CODE BEGIN Includes */
#include "settings.h"
#include "lcd_driver.h"
#include "functions.h"
#include "bootloader.h"
#include "trx_manager.h"
#include "lcd.h"
#include "front_unit.h"
#include "rf_unit.h"
#include "fpga.h"
#include "fft.h"
#include "wm8731.h"
#include "audio_processor.h"
#include "profiler.h"
#include "usb_device.h"
#include "usbd_cat_if.h"
#include "usbd_debug_if.h"
#include "wifi.h"
#include "images.h"
#include "sd.h"
/* USER CODE END Includes */

 ADC_HandleTypeDef hadc1;
ADC_HandleTypeDef hadc2;
ADC_HandleTypeDef hadc3;

CRC_HandleTypeDef hcrc;

I2S_HandleTypeDef hi2s3;

IWDG_HandleTypeDef hiwdg1;

RTC_HandleTypeDef hrtc;

SPI_HandleTypeDef hspi2;
SPI_HandleTypeDef hspi4;
DMA_HandleTypeDef hdma_spi2_rx;
DMA_HandleTypeDef hdma_spi2_tx;
DMA_HandleTypeDef hdma_spi4_tx;

TIM_HandleTypeDef htim2;
TIM_HandleTypeDef htim3;
TIM_HandleTypeDef htim4;
TIM_HandleTypeDef htim5;
TIM_HandleTypeDef htim6;
TIM_HandleTypeDef htim7;
TIM_HandleTypeDef htim15;
TIM_HandleTypeDef htim16;
TIM_HandleTypeDef htim17;

UART_HandleTypeDef huart6;
DMA_HandleTypeDef hdma_usart6_rx;

PCD_HandleTypeDef hpcd_USB_OTG_FS;

MDMA_HandleTypeDef hmdma_mdma_channel40_sw_0;
MDMA_HandleTypeDef hmdma_mdma_channel41_sw_0;
MDMA_HandleTypeDef hmdma_mdma_channel42_sw_0;
MDMA_HandleTypeDef hmdma_mdma_channel43_sw_0;
MDMA_HandleTypeDef hmdma_mdma_channel44_sw_0;
/* USER CODE BEGIN PV */
DMA_HandleTypeDef hdma_spi3_tx;
DMA_HandleTypeDef hdma_spi3_rx;
static char greetings_buff[32] = {0};
/* USER CODE END PV */

void SystemClock_Config(void);
static void MPU_Config(void);
static void MX_GPIO_Init(void);
static void MX_DMA_Init(void);
static void MX_MDMA_Init(void);
static void MX_ADC1_Init(void);
static void MX_I2S3_Init(void);
static void MX_RTC_Init(void);
static void MX_SPI2_Init(void);
static void MX_TIM3_Init(void);
static void MX_TIM4_Init(void);
static void MX_TIM5_Init(void);
static void MX_TIM6_Init(void);
static void MX_TIM7_Init(void);
static void MX_USB_OTG_FS_PCD_Init(void);
static void MX_ADC3_Init(void);
static void MX_TIM15_Init(void);
static void MX_TIM16_Init(void);
static void MX_TIM17_Init(void);
static void MX_TIM2_Init(void);
static void MX_CRC_Init(void);
static void MX_SPI4_Init(void);
static void MX_USART6_UART_Init(void);
static void MX_IWDG1_Init(void);
static void MX_ADC2_Init(void);

int main(void)
{
  /* USER CODE BEGIN 1 */
  MX_GPIO_Init(); // pwr hold
  /* USER CODE END 1 */

  /* MPU Configuration--------------------------------------------------------*/
  MPU_Config();

  /* Enable I-Cache---------------------------------------------------------*/
  SCB_EnableICache();

  /* Enable D-Cache---------------------------------------------------------*/
  SCB_EnableDCache();

  /* MCU Configuration--------------------------------------------------------*/

  /* Reset of all peripherals, Initializes the Flash interface and the Systick. */
  HAL_Init();

  /* Configure the system clock */
  SystemClock_Config();

  /* USER CODE BEGIN SysInit */
  //System stabilization
  uint8_t tryes = 0;
  //while (tryes < 3 && (!__HAL_PWR_GET_FLAG(PWR_FLAG_VOSRDY) || (RCC->CR & RCC_CR_HSERDY) == 0 || (RCC->CR & RCC_CR_PLL1RDY) == 0 || (RCC->CR & RCC_CR_PLL2RDY) == 0 || (RCC->CR & RCC_CR_PLL3RDY) == 0 || (RCC->CFGR & RCC_CFGR_SWS) != RCC_CFGR_SWS_PLL1))
  while (tryes < 3 && (!__HAL_PWR_GET_FLAG(PWR_FLAG_VOSRDY) || (RCC->CR & RCC_CR_HSERDY) == 0 || (RCC->BDCR & RCC_BDCR_LSERDY) == 0 || (RCC->CR & RCC_CR_PLL1RDY) == 0 || (RCC->CFGR & RCC_CFGR_SWS) != RCC_CFGR_SWS_PLL1))
  {
    SystemClock_Config();
    tryes++;
  }
  if (tryes == 3)
  {
    LCD_Init();
    LCD_showError("STM32 crystals error", false);
  }

//Stack protection
#define stack_addr 0x20000000
  MPU_Region_InitTypeDef MPU_InitStruct = {0};
  MPU_InitStruct.Enable = MPU_REGION_ENABLE;
  MPU_InitStruct.Number = MPU_REGION_NUMBER4;
  MPU_InitStruct.BaseAddress = stack_addr + 256; //growning down
  MPU_InitStruct.Size = MPU_REGION_SIZE_32B;
  MPU_InitStruct.SubRegionDisable = 0x0;
  MPU_InitStruct.TypeExtField = MPU_TEX_LEVEL0;
  MPU_InitStruct.AccessPermission = MPU_REGION_NO_ACCESS;
  MPU_InitStruct.DisableExec = MPU_INSTRUCTION_ACCESS_ENABLE;
  MPU_InitStruct.IsShareable = MPU_ACCESS_NOT_SHAREABLE;
  MPU_InitStruct.IsCacheable = MPU_ACCESS_NOT_CACHEABLE;
  MPU_InitStruct.IsBufferable = MPU_ACCESS_NOT_BUFFERABLE;
  HAL_MPU_ConfigRegion(&MPU_InitStruct);

  /* USER CODE END SysInit */

  /* Initialize all configured peripherals */
  MX_GPIO_Init();
  MX_DMA_Init();
  MX_MDMA_Init();
  MX_ADC1_Init();
  MX_I2S3_Init();
  MX_RTC_Init();
  MX_SPI2_Init();
  MX_TIM3_Init();
  MX_TIM4_Init();
  MX_TIM5_Init();
  MX_TIM6_Init();
  MX_TIM7_Init();
  MX_ADC3_Init();
  MX_TIM15_Init();
  MX_TIM16_Init();
  MX_TIM17_Init();
  MX_FATFS_Init();
  MX_TIM2_Init();
  MX_CRC_Init();
  MX_SPI4_Init();
  MX_USART6_UART_Init();
  MX_ADC2_Init();
  /* USER CODE BEGIN 2 */
#ifdef HAS_TOUCHPAD
  GPIO_InitTypeDef GPIO_InitStruct = {0};
  GPIO_InitStruct.Pin = ENC2SW_AND_TOUCHPAD_Pin;
  GPIO_InitStruct.Mode = GPIO_MODE_INPUT;
  GPIO_InitStruct.Pull = GPIO_PULLDOWN;
  HAL_GPIO_Init(GPIOE, &GPIO_InitStruct);
#endif
  __HAL_RCC_CSI_ENABLE();
  __HAL_RCC_SYSCFG_CLK_ENABLE();
  __HAL_RCC_BKPRAM_CLK_ENABLE();
  HAL_EnableCompensationCell();
  println("\r\n----------------------------------");
  println("Wolf Transceiver Initialization...");
  println("[OK] USB init");
  USBD_Restart();
  println("[OK] FIFO timer TIM7 init");
  HAL_TIM_Base_Start_IT(&htim7);
	println("[OK] ENC2 timer TIM16 init");
  HAL_TIM_Base_Start_IT(&htim16);
  println("[OK] Real Time Clock init");
  HAL_RTC_Init(&hrtc);
  println("[OK] Frontpanel init");
	HAL_Delay(500);
  FRONTPANEL_Init();

  println("[OK] Settings loading");
  if (PERIPH_FrontPanel_Buttons[0].state) //soft reset (MENU)
	{
		println("MENU Button pressed");
    LoadSettings(true);
	}
  else
    LoadSettings(false);

	//DFU bootloader
	if (TRX.NeedGoToBootloader || PERIPH_FrontPanel_Buttons[5].state)
	{
		TRX.NeedGoToBootloader = false;
		SaveSettings();
    JumpToBootloader();
	}
	else
	{
		MX_IWDG1_Init();
	}

  TRX.Locked = false;
  println("[OK] LCD init");
  LCD_busy = true;
  LCD_Init();
	LCD_Init();
  if (SHOW_LOGO)
  {
    LCDDriver_Fill(rgb888torgb565(243, 243, 243));
    LCDDriver_printImage_RLECompressed(((LCD_WIDTH - IMAGES_logo160.width) / 2), ((LCD_HEIGHT - IMAGES_logo160.height) / 2), &IMAGES_logo160, BG_COLOR, BG_COLOR);
    strcpy(greetings_buff, "ver. ");
    strcat(greetings_buff, version_string);
		LCDDriver_printText(greetings_buff, 4, (LCD_HEIGHT - 10), COLOR_RED, rgb888torgb565(243, 243, 243), 1);
    //show callsign greetings
    uint16_t x1, y1, w, h;
    strcpy(greetings_buff, "Hello, ");
    strcat(greetings_buff, TRX.CALLSIGN);
    strcat(greetings_buff, " !");
    LCDDriver_getTextBounds(greetings_buff, LAYOUT->GREETINGS_X, LAYOUT->GREETINGS_Y, &x1, &y1, &w, &h, 1);
    LCDDriver_printText(greetings_buff, LAYOUT->GREETINGS_X - (w / 2), LAYOUT->GREETINGS_Y, COLOR->GREETINGS, rgb888torgb565(243, 243, 243), 1);
  }
  println("[OK] Profiler init");
  InitProfiler();

  println("[OK] Calibration loading");
  if (PERIPH_FrontPanel_Buttons[2].state && PERIPH_FrontPanel_Buttons[0].state) //Very hard reset (MENU+F4)
    LoadCalibration(true);
  else
    LoadCalibration(false);

	sd_crc_generate_table();

	println("[OK] Profiler init");
  InitProfiler();

  println("[OK] RTC calibration");
  RTC_Calibration();

  println("[OK] RF-Unit init");
  RF_UNIT_UpdateState(false);
  println("[OK] FFT/Waterfall & ADC & TIM4 init");
  FFT_PreInit();
  FFT_Init();
  HAL_TIM_Base_Start_IT(&htim4);
	println("[OK] STM32-ADC Calibration");
  HAL_ADCEx_Calibration_Start(&hadc1, LL_ADC_CALIB_OFFSET_LINEARITY, ADC_SINGLE_ENDED);
	HAL_ADCEx_Calibration_Start(&hadc2, LL_ADC_CALIB_OFFSET_LINEARITY, ADC_SINGLE_ENDED);
  HAL_ADCEx_Calibration_Start(&hadc3, LL_ADC_CALIB_OFFSET_LINEARITY, ADC_SINGLE_ENDED);
  println("[OK] AudioCodec init");
  WM8731_Init();
  println("[OK] TRX init");
  TRX_Init();
  println("[OK] Audioprocessor & TIM5 init");
  initAudioProcessor();
  HAL_TIM_Base_Start_IT(&htim5);
  if (SHOW_LOGO)
    HAL_Delay(1000); //logo wait
  LCD_busy = false;
  LCD_redraw(true);
  println("[OK] Misc timer TIM6 init");
  HAL_TIM_Base_Start_IT(&htim6);
  println("[OK] CPU Load init");
  CPULOAD_Init();
  println("[OK] PERIPHERAL timer TIM15 init");
  dma_memset(&SDFatFs, 0, sizeof(SDFatFs));
  HAL_TIM_Base_Start_IT(&htim15);
  println("[OK] Digital decoder timer TIM17 init");
  HAL_TIM_Base_Start_IT(&htim17);
	println("[OK] FPGA init");
#ifdef FRONTPANEL_SMALL_V1
  if (PERIPH_FrontPanel_Buttons[19].state) //fpga bus test (MODE+)
    FPGA_Init(true, false);
  if (PERIPH_FrontPanel_Buttons[20].state) //fpga firmware test (MODE-)
    FPGA_Init(false, true);
  else
#endif
  FPGA_Init(false, false);
	println("[OK] WIFI timer TIM3 init");
  HAL_TIM_Base_Start_IT(&htim3);
  println("UA3REO Transceiver started!\r\n");
	TRX_Inited = true;

  //while(true){HAL_Delay(3000); SCB->AIRCR = 0x05FA0004; } //debug restart

  /* USER CODE END 2 */

  /* Infinite loop */
  while (1)
  {

    /* USER CODE BEGIN 3 */
    CPULOAD_GoToSleepMode();
  }
  /* USER CODE END 3 */
}

void SystemClock_Config(void)
{
  RCC_OscInitTypeDef RCC_OscInitStruct = {0};
  RCC_ClkInitTypeDef RCC_ClkInitStruct = {0};

  /** Supply configuration update enable
  */
  HAL_PWREx_ConfigSupply(PWR_LDO_SUPPLY);

  /** Configure the main internal regulator output voltage
  */
  __HAL_PWR_VOLTAGESCALING_CONFIG(PWR_REGULATOR_VOLTAGE_SCALE0);

  while(!__HAL_PWR_GET_FLAG(PWR_FLAG_VOSRDY)) {}

  /** Configure LSE Drive Capability
  */
  HAL_PWR_EnableBkUpAccess();
  __HAL_RCC_LSEDRIVE_CONFIG(RCC_LSEDRIVE_HIGH);

  /** Macro to configure the PLL clock source
  */
  __HAL_RCC_PLL_PLLSOURCE_CONFIG(RCC_PLLSOURCE_HSE);

  /** Initializes the RCC Oscillators according to the specified parameters
  * in the RCC_OscInitTypeDef structure.
  */
  RCC_OscInitStruct.OscillatorType = RCC_OSCILLATORTYPE_LSI|RCC_OSCILLATORTYPE_HSE
                              |RCC_OSCILLATORTYPE_LSE;
  RCC_OscInitStruct.HSEState = RCC_HSE_ON;
  RCC_OscInitStruct.LSEState = RCC_LSE_ON;
  RCC_OscInitStruct.LSIState = RCC_LSI_ON;
  RCC_OscInitStruct.PLL.PLLState = RCC_PLL_ON;
  RCC_OscInitStruct.PLL.PLLSource = RCC_PLLSOURCE_HSE;
  RCC_OscInitStruct.PLL.PLLM = 2;
  RCC_OscInitStruct.PLL.PLLN = 240;
  RCC_OscInitStruct.PLL.PLLP = 2;
  RCC_OscInitStruct.PLL.PLLQ = 2;
  RCC_OscInitStruct.PLL.PLLR = 2;
  RCC_OscInitStruct.PLL.PLLRGE = RCC_PLL1VCIRANGE_2;
  RCC_OscInitStruct.PLL.PLLVCOSEL = RCC_PLL1VCOWIDE;
  RCC_OscInitStruct.PLL.PLLFRACN = 0;
  if (HAL_RCC_OscConfig(&RCC_OscInitStruct) != HAL_OK)
  {
    Error_Handler();
  }

  /** Initializes the CPU, AHB and APB buses clocks
  */
  RCC_ClkInitStruct.ClockType = RCC_CLOCKTYPE_HCLK|RCC_CLOCKTYPE_SYSCLK
                              |RCC_CLOCKTYPE_PCLK1|RCC_CLOCKTYPE_PCLK2
                              |RCC_CLOCKTYPE_D3PCLK1|RCC_CLOCKTYPE_D1PCLK1;
  RCC_ClkInitStruct.SYSCLKSource = RCC_SYSCLKSOURCE_PLLCLK;
  RCC_ClkInitStruct.SYSCLKDivider = RCC_SYSCLK_DIV1;
  RCC_ClkInitStruct.AHBCLKDivider = RCC_HCLK_DIV2;
  RCC_ClkInitStruct.APB3CLKDivider = RCC_APB3_DIV2;
  RCC_ClkInitStruct.APB1CLKDivider = RCC_APB1_DIV2;
  RCC_ClkInitStruct.APB2CLKDivider = RCC_APB2_DIV2;
  RCC_ClkInitStruct.APB4CLKDivider = RCC_APB4_DIV2;

  if (HAL_RCC_ClockConfig(&RCC_ClkInitStruct, FLASH_LATENCY_4) != HAL_OK)
  {
    Error_Handler();
  }
}

static void MX_ADC1_Init(void)
{

  ADC_MultiModeTypeDef multimode = {0};
  ADC_InjectionConfTypeDef sConfigInjected = {0};

  /** Common config
  */
  hadc1.Instance = ADC1;
  hadc1.Init.ClockPrescaler = ADC_CLOCK_ASYNC_DIV256;
  hadc1.Init.Resolution = ADC_RESOLUTION_16B;
  hadc1.Init.ScanConvMode = ADC_SCAN_ENABLE;
  hadc1.Init.EOCSelection = ADC_EOC_SEQ_CONV;
  hadc1.Init.LowPowerAutoWait = DISABLE;
  hadc1.Init.ContinuousConvMode = ENABLE;
  hadc1.Init.NbrOfConversion = 1;
  hadc1.Init.DiscontinuousConvMode = DISABLE;
  hadc1.Init.ConversionDataManagement = ADC_CONVERSIONDATA_DR;
  hadc1.Init.Overrun = ADC_OVR_DATA_OVERWRITTEN;
  hadc1.Init.LeftBitShift = ADC_LEFTBITSHIFT_NONE;
  hadc1.Init.OversamplingMode = DISABLE;
  if (HAL_ADC_Init(&hadc1) != HAL_OK)
  {
    Error_Handler();
  }

  /** Configure the ADC multi-mode
  */
  multimode.Mode = ADC_MODE_INDEPENDENT;
  if (HAL_ADCEx_MultiModeConfigChannel(&hadc1, &multimode) != HAL_OK)
  {
    Error_Handler();
  }

  /** Disable Injected Queue
  */
  HAL_ADCEx_DisableInjectedQueue(&hadc1);

  /** Configure Injected Channel
  */
  sConfigInjected.InjectedChannel = ADC_CHANNEL_11;
  sConfigInjected.InjectedRank = ADC_INJECTED_RANK_1;
  sConfigInjected.InjectedSamplingTime = ADC_SAMPLETIME_1CYCLE_5;
  sConfigInjected.InjectedSingleDiff = ADC_SINGLE_ENDED;
  sConfigInjected.InjectedOffsetNumber = ADC_OFFSET_NONE;
  sConfigInjected.InjectedOffset = 0;
  sConfigInjected.InjectedNbrOfConversion = 2;
  sConfigInjected.InjectedDiscontinuousConvMode = DISABLE;
  sConfigInjected.AutoInjectedConv = DISABLE;
  sConfigInjected.QueueInjectedContext = DISABLE;
  sConfigInjected.ExternalTrigInjecConv = ADC_EXTERNALTRIGINJEC_T4_TRGO;
  sConfigInjected.ExternalTrigInjecConvEdge = ADC_EXTERNALTRIGINJECCONV_EDGE_RISING;
  sConfigInjected.InjecOversamplingMode = DISABLE;
  if (HAL_ADCEx_InjectedConfigChannel(&hadc1, &sConfigInjected) != HAL_OK)
  {
    Error_Handler();
  }

  /** Configure Injected Channel
  */
  sConfigInjected.InjectedChannel = ADC_CHANNEL_10;
  sConfigInjected.InjectedRank = ADC_INJECTED_RANK_2;
  if (HAL_ADCEx_InjectedConfigChannel(&hadc1, &sConfigInjected) != HAL_OK)
  {
    Error_Handler();
  }

}

static void MX_ADC2_Init(void)
{

  ADC_InjectionConfTypeDef sConfigInjected = {0};

  /** Common config
  */
  hadc2.Instance = ADC2;
  hadc2.Init.ClockPrescaler = ADC_CLOCK_ASYNC_DIV256;
  hadc2.Init.Resolution = ADC_RESOLUTION_16B;
  hadc2.Init.ScanConvMode = ADC_SCAN_ENABLE;
  hadc2.Init.EOCSelection = ADC_EOC_SEQ_CONV;
  hadc2.Init.LowPowerAutoWait = DISABLE;
  hadc2.Init.ContinuousConvMode = ENABLE;
  hadc2.Init.NbrOfConversion = 1;
  hadc2.Init.DiscontinuousConvMode = DISABLE;
  hadc2.Init.ConversionDataManagement = ADC_CONVERSIONDATA_DR;
  hadc2.Init.Overrun = ADC_OVR_DATA_OVERWRITTEN;
  hadc2.Init.LeftBitShift = ADC_LEFTBITSHIFT_NONE;
  hadc2.Init.OversamplingMode = DISABLE;
  if (HAL_ADC_Init(&hadc2) != HAL_OK)
  {
    Error_Handler();
  }

  /** Disable Injected Queue
  */
  HAL_ADCEx_DisableInjectedQueue(&hadc2);

  /** Configure Injected Channel
  */
  sConfigInjected.InjectedChannel = ADC_CHANNEL_9;
  sConfigInjected.InjectedRank = ADC_INJECTED_RANK_1;
  sConfigInjected.InjectedSamplingTime = ADC_SAMPLETIME_32CYCLES_5;
  sConfigInjected.InjectedSingleDiff = ADC_SINGLE_ENDED;
  sConfigInjected.InjectedOffsetNumber = ADC_OFFSET_NONE;
  sConfigInjected.InjectedOffset = 0;
  sConfigInjected.InjectedNbrOfConversion = 4;
  sConfigInjected.InjectedDiscontinuousConvMode = DISABLE;
  sConfigInjected.AutoInjectedConv = DISABLE;
  sConfigInjected.QueueInjectedContext = DISABLE;
  sConfigInjected.ExternalTrigInjecConv = ADC_EXTERNALTRIGINJEC_T4_TRGO;
  sConfigInjected.ExternalTrigInjecConvEdge = ADC_EXTERNALTRIGINJECCONV_EDGE_RISING;
  sConfigInjected.InjecOversamplingMode = DISABLE;
  if (HAL_ADCEx_InjectedConfigChannel(&hadc2, &sConfigInjected) != HAL_OK)
  {
    Error_Handler();
  }

  /** Configure Injected Channel
  */
  sConfigInjected.InjectedChannel = ADC_CHANNEL_5;
  sConfigInjected.InjectedRank = ADC_INJECTED_RANK_2;
  if (HAL_ADCEx_InjectedConfigChannel(&hadc2, &sConfigInjected) != HAL_OK)
  {
    Error_Handler();
  }

  /** Configure Injected Channel
  */
  sConfigInjected.InjectedChannel = ADC_CHANNEL_8;
  sConfigInjected.InjectedRank = ADC_INJECTED_RANK_3;
  if (HAL_ADCEx_InjectedConfigChannel(&hadc2, &sConfigInjected) != HAL_OK)
  {
    Error_Handler();
  }

  /** Configure Injected Channel
  */
  sConfigInjected.InjectedChannel = ADC_CHANNEL_5;
  sConfigInjected.InjectedRank = ADC_INJECTED_RANK_4;
  sConfigInjected.InjectedSamplingTime = ADC_SAMPLETIME_1CYCLE_5;
  if (HAL_ADCEx_InjectedConfigChannel(&hadc2, &sConfigInjected) != HAL_OK)
  {
    Error_Handler();
  }

}

static void MX_ADC3_Init(void)
{

  ADC_InjectionConfTypeDef sConfigInjected = {0};

  /** Common config
  */
  hadc3.Instance = ADC3;
  hadc3.Init.ClockPrescaler = ADC_CLOCK_ASYNC_DIV256;
  hadc3.Init.Resolution = ADC_RESOLUTION_16B;
  hadc3.Init.ScanConvMode = ADC_SCAN_ENABLE;
  hadc3.Init.EOCSelection = ADC_EOC_SEQ_CONV;
  hadc3.Init.LowPowerAutoWait = DISABLE;
  hadc3.Init.ContinuousConvMode = ENABLE;
  hadc3.Init.NbrOfConversion = 1;
  hadc3.Init.DiscontinuousConvMode = DISABLE;
  hadc3.Init.ConversionDataManagement = ADC_CONVERSIONDATA_DR;
  hadc3.Init.Overrun = ADC_OVR_DATA_OVERWRITTEN;
  hadc3.Init.LeftBitShift = ADC_LEFTBITSHIFT_NONE;
  hadc3.Init.OversamplingMode = DISABLE;
  if (HAL_ADC_Init(&hadc3) != HAL_OK)
  {
    Error_Handler();
  }

  /** Disable Injected Queue
  */
  HAL_ADCEx_DisableInjectedQueue(&hadc3);

  /** Configure Injected Channel
  */
  sConfigInjected.InjectedChannel = ADC_CHANNEL_TEMPSENSOR;
  sConfigInjected.InjectedRank = ADC_INJECTED_RANK_1;
  sConfigInjected.InjectedSamplingTime = ADC_SAMPLETIME_810CYCLES_5;
  sConfigInjected.InjectedSingleDiff = ADC_SINGLE_ENDED;
  sConfigInjected.InjectedOffsetNumber = ADC_OFFSET_NONE;
  sConfigInjected.InjectedOffset = 0;
  sConfigInjected.InjectedNbrOfConversion = 3;
  sConfigInjected.InjectedDiscontinuousConvMode = DISABLE;
  sConfigInjected.AutoInjectedConv = DISABLE;
  sConfigInjected.QueueInjectedContext = DISABLE;
  sConfigInjected.ExternalTrigInjecConv = ADC_EXTERNALTRIGINJEC_T4_TRGO;
  sConfigInjected.ExternalTrigInjecConvEdge = ADC_EXTERNALTRIGINJECCONV_EDGE_RISING;
  sConfigInjected.InjecOversamplingMode = DISABLE;
  if (HAL_ADCEx_InjectedConfigChannel(&hadc3, &sConfigInjected) != HAL_OK)
  {
    Error_Handler();
  }

  /** Configure Injected Channel
  */
  sConfigInjected.InjectedChannel = ADC_CHANNEL_VREFINT;
  sConfigInjected.InjectedRank = ADC_INJECTED_RANK_2;
  if (HAL_ADCEx_InjectedConfigChannel(&hadc3, &sConfigInjected) != HAL_OK)
  {
    Error_Handler();
  }

  /** Configure Injected Channel
  */
  sConfigInjected.InjectedChannel = ADC_CHANNEL_VBAT;
  sConfigInjected.InjectedRank = ADC_INJECTED_RANK_3;
  if (HAL_ADCEx_InjectedConfigChannel(&hadc3, &sConfigInjected) != HAL_OK)
  {
    Error_Handler();
  }

}

static void MX_CRC_Init(void)
{

  hcrc.Instance = CRC;
  hcrc.Init.DefaultPolynomialUse = DEFAULT_POLYNOMIAL_ENABLE;
  hcrc.Init.DefaultInitValueUse = DEFAULT_INIT_VALUE_ENABLE;
  hcrc.Init.InputDataInversionMode = CRC_INPUTDATA_INVERSION_NONE;
  hcrc.Init.OutputDataInversionMode = CRC_OUTPUTDATA_INVERSION_DISABLE;
  hcrc.InputDataFormat = CRC_INPUTDATA_FORMAT_BYTES;
  if (HAL_CRC_Init(&hcrc) != HAL_OK)
  {
    Error_Handler();
  }

}

static void MX_I2S3_Init(void)
{

  hi2s3.Instance = SPI3;
  hi2s3.Init.Mode = I2S_MODE_MASTER_FULLDUPLEX;
  hi2s3.Init.Standard = I2S_STANDARD_PHILIPS;
  hi2s3.Init.DataFormat = I2S_DATAFORMAT_32B;
  hi2s3.Init.MCLKOutput = I2S_MCLKOUTPUT_DISABLE;
  hi2s3.Init.AudioFreq = I2S_AUDIOFREQ_48K;
  hi2s3.Init.CPOL = I2S_CPOL_LOW;
  hi2s3.Init.FirstBit = I2S_FIRSTBIT_MSB;
  hi2s3.Init.WSInversion = I2S_WS_INVERSION_DISABLE;
  hi2s3.Init.Data24BitAlignment = I2S_DATA_24BIT_ALIGNMENT_RIGHT;
  hi2s3.Init.MasterKeepIOState = I2S_MASTER_KEEP_IO_STATE_ENABLE;
  if (HAL_I2S_Init(&hi2s3) != HAL_OK)
  {
    Error_Handler();
  }
  /* USER CODE BEGIN I2S3_Init 2 */
  //перевод I2S в режим full-duplex
  hi2s3.Init.Mode = I2S_MODE_MASTER_FULLDUPLEX;
  if (HAL_I2S_Init(&hi2s3) != HAL_OK)
  {
    Error_Handler();
  }
  /* USER CODE END I2S3_Init 2 */

}

static void MX_IWDG1_Init(void)
{

  hiwdg1.Instance = IWDG1;
  hiwdg1.Init.Prescaler = IWDG_PRESCALER_4;
  hiwdg1.Init.Window = 1500;
  hiwdg1.Init.Reload = 1500;
  if (HAL_IWDG_Init(&hiwdg1) != HAL_OK)
  {
    Error_Handler();
  }

}

static void MX_RTC_Init(void)
{

  /** Initialize RTC Only
  */
  hrtc.Instance = RTC;
  hrtc.Init.HourFormat = RTC_HOURFORMAT_24;
  hrtc.Init.AsynchPrediv = 127;
  hrtc.Init.SynchPrediv = 255;
  hrtc.Init.OutPut = RTC_OUTPUT_DISABLE;
  hrtc.Init.OutPutPolarity = RTC_OUTPUT_POLARITY_HIGH;
  hrtc.Init.OutPutType = RTC_OUTPUT_TYPE_OPENDRAIN;
  hrtc.Init.OutPutRemap = RTC_OUTPUT_REMAP_NONE;
  if (HAL_RTC_Init(&hrtc) != HAL_OK)
  {
    Error_Handler();
  }

}

static void MX_SPI2_Init(void)
{

  /* SPI2 parameter configuration*/
  hspi2.Instance = SPI2;
  hspi2.Init.Mode = SPI_MODE_MASTER;
  hspi2.Init.Direction = SPI_DIRECTION_2LINES;
  hspi2.Init.DataSize = SPI_DATASIZE_8BIT;
  hspi2.Init.CLKPolarity = SPI_POLARITY_LOW;
  hspi2.Init.CLKPhase = SPI_PHASE_1EDGE;
  hspi2.Init.NSS = SPI_NSS_SOFT;
  hspi2.Init.BaudRatePrescaler = SPI_BAUDRATEPRESCALER_2;
  hspi2.Init.FirstBit = SPI_FIRSTBIT_MSB;
  hspi2.Init.TIMode = SPI_TIMODE_DISABLE;
  hspi2.Init.CRCCalculation = SPI_CRCCALCULATION_DISABLE;
  hspi2.Init.CRCPolynomial = 0x0;
  hspi2.Init.NSSPMode = SPI_NSS_PULSE_DISABLE;
  hspi2.Init.NSSPolarity = SPI_NSS_POLARITY_LOW;
  hspi2.Init.FifoThreshold = SPI_FIFO_THRESHOLD_01DATA;
  hspi2.Init.TxCRCInitializationPattern = SPI_CRC_INITIALIZATION_ALL_ZERO_PATTERN;
  hspi2.Init.RxCRCInitializationPattern = SPI_CRC_INITIALIZATION_ALL_ZERO_PATTERN;
  hspi2.Init.MasterSSIdleness = SPI_MASTER_SS_IDLENESS_00CYCLE;
  hspi2.Init.MasterInterDataIdleness = SPI_MASTER_INTERDATA_IDLENESS_00CYCLE;
  hspi2.Init.MasterReceiverAutoSusp = SPI_MASTER_RX_AUTOSUSP_DISABLE;
  hspi2.Init.MasterKeepIOState = SPI_MASTER_KEEP_IO_STATE_DISABLE;
  hspi2.Init.IOSwap = SPI_IO_SWAP_DISABLE;
  if (HAL_SPI_Init(&hspi2) != HAL_OK)
  {
    Error_Handler();
  }

}

static void MX_SPI4_Init(void)
{

  /* SPI4 parameter configuration*/
  hspi4.Instance = SPI4;
  hspi4.Init.Mode = SPI_MODE_MASTER;
  hspi4.Init.Direction = SPI_DIRECTION_2LINES;
  hspi4.Init.DataSize = SPI_DATASIZE_8BIT;
  hspi4.Init.CLKPolarity = SPI_POLARITY_LOW;
  hspi4.Init.CLKPhase = SPI_PHASE_1EDGE;
  hspi4.Init.NSS = SPI_NSS_HARD_OUTPUT;
  hspi4.Init.BaudRatePrescaler = SPI_BAUDRATEPRESCALER_4;
  hspi4.Init.FirstBit = SPI_FIRSTBIT_MSB;
  hspi4.Init.TIMode = SPI_TIMODE_DISABLE;
  hspi4.Init.CRCCalculation = SPI_CRCCALCULATION_DISABLE;
  hspi4.Init.CRCPolynomial = 0x0;
  hspi4.Init.NSSPMode = SPI_NSS_PULSE_ENABLE;
  hspi4.Init.NSSPolarity = SPI_NSS_POLARITY_LOW;
  hspi4.Init.FifoThreshold = SPI_FIFO_THRESHOLD_01DATA;
  hspi4.Init.TxCRCInitializationPattern = SPI_CRC_INITIALIZATION_ALL_ZERO_PATTERN;
  hspi4.Init.RxCRCInitializationPattern = SPI_CRC_INITIALIZATION_ALL_ZERO_PATTERN;
  hspi4.Init.MasterSSIdleness = SPI_MASTER_SS_IDLENESS_00CYCLE;
  hspi4.Init.MasterInterDataIdleness = SPI_MASTER_INTERDATA_IDLENESS_00CYCLE;
  hspi4.Init.MasterReceiverAutoSusp = SPI_MASTER_RX_AUTOSUSP_DISABLE;
  hspi4.Init.MasterKeepIOState = SPI_MASTER_KEEP_IO_STATE_DISABLE;
  hspi4.Init.IOSwap = SPI_IO_SWAP_DISABLE;
  if (HAL_SPI_Init(&hspi4) != HAL_OK)
  {
    Error_Handler();
  }

}

static void MX_TIM2_Init(void)
{

  TIM_ClockConfigTypeDef sClockSourceConfig = {0};
  TIM_MasterConfigTypeDef sMasterConfig = {0};

  htim2.Instance = TIM2;
  htim2.Init.Prescaler = 16341;
  htim2.Init.CounterMode = TIM_COUNTERMODE_UP;
  htim2.Init.Period = 10025;
  htim2.Init.ClockDivision = TIM_CLOCKDIVISION_DIV1;
  htim2.Init.AutoReloadPreload = TIM_AUTORELOAD_PRELOAD_DISABLE;
  if (HAL_TIM_Base_Init(&htim2) != HAL_OK)
  {
    Error_Handler();
  }
  sClockSourceConfig.ClockSource = TIM_CLOCKSOURCE_INTERNAL;
  if (HAL_TIM_ConfigClockSource(&htim2, &sClockSourceConfig) != HAL_OK)
  {
    Error_Handler();
  }
  sMasterConfig.MasterOutputTrigger = TIM_TRGO_UPDATE;
  sMasterConfig.MasterSlaveMode = TIM_MASTERSLAVEMODE_DISABLE;
  if (HAL_TIMEx_MasterConfigSynchronization(&htim2, &sMasterConfig) != HAL_OK)
  {
    Error_Handler();
  }

}

static void MX_TIM3_Init(void)
{

  TIM_ClockConfigTypeDef sClockSourceConfig = {0};
  TIM_MasterConfigTypeDef sMasterConfig = {0};

  htim3.Instance = TIM3;
  htim3.Init.Prescaler = 1199;
  htim3.Init.CounterMode = TIM_COUNTERMODE_UP;
  htim3.Init.Period = 199;
  htim3.Init.ClockDivision = TIM_CLOCKDIVISION_DIV1;
  htim3.Init.AutoReloadPreload = TIM_AUTORELOAD_PRELOAD_DISABLE;
  if (HAL_TIM_Base_Init(&htim3) != HAL_OK)
  {
    Error_Handler();
  }
  sClockSourceConfig.ClockSource = TIM_CLOCKSOURCE_INTERNAL;
  if (HAL_TIM_ConfigClockSource(&htim3, &sClockSourceConfig) != HAL_OK)
  {
    Error_Handler();
  }
  sMasterConfig.MasterOutputTrigger = TIM_TRGO_UPDATE;
  sMasterConfig.MasterSlaveMode = TIM_MASTERSLAVEMODE_DISABLE;
  if (HAL_TIMEx_MasterConfigSynchronization(&htim3, &sMasterConfig) != HAL_OK)
  {
    Error_Handler();
  }

}

static void MX_TIM4_Init(void)
{

  TIM_ClockConfigTypeDef sClockSourceConfig = {0};
  TIM_MasterConfigTypeDef sMasterConfig = {0};

  htim4.Instance = TIM4;
  htim4.Init.Prescaler = 1199;
  htim4.Init.CounterMode = TIM_COUNTERMODE_UP;
  htim4.Init.Period = 199;
  htim4.Init.ClockDivision = TIM_CLOCKDIVISION_DIV1;
  htim4.Init.AutoReloadPreload = TIM_AUTORELOAD_PRELOAD_DISABLE;
  if (HAL_TIM_Base_Init(&htim4) != HAL_OK)
  {
    Error_Handler();
  }
  sClockSourceConfig.ClockSource = TIM_CLOCKSOURCE_INTERNAL;
  if (HAL_TIM_ConfigClockSource(&htim4, &sClockSourceConfig) != HAL_OK)
  {
    Error_Handler();
  }
  sMasterConfig.MasterOutputTrigger = TIM_TRGO_UPDATE;
  sMasterConfig.MasterSlaveMode = TIM_MASTERSLAVEMODE_DISABLE;
  if (HAL_TIMEx_MasterConfigSynchronization(&htim4, &sMasterConfig) != HAL_OK)
  {
    Error_Handler();
  }

}

static void MX_TIM5_Init(void)
{

  TIM_ClockConfigTypeDef sClockSourceConfig = {0};
  TIM_MasterConfigTypeDef sMasterConfig = {0};

  htim5.Instance = TIM5;
  htim5.Init.Prescaler = 119;
  htim5.Init.CounterMode = TIM_COUNTERMODE_UP;
  htim5.Init.Period = 99;
  htim5.Init.ClockDivision = TIM_CLOCKDIVISION_DIV1;
  htim5.Init.AutoReloadPreload = TIM_AUTORELOAD_PRELOAD_DISABLE;
  if (HAL_TIM_Base_Init(&htim5) != HAL_OK)
  {
    Error_Handler();
  }
  sClockSourceConfig.ClockSource = TIM_CLOCKSOURCE_INTERNAL;
  if (HAL_TIM_ConfigClockSource(&htim5, &sClockSourceConfig) != HAL_OK)
  {
    Error_Handler();
  }
  sMasterConfig.MasterOutputTrigger = TIM_TRGO_UPDATE;
  sMasterConfig.MasterSlaveMode = TIM_MASTERSLAVEMODE_DISABLE;
  if (HAL_TIMEx_MasterConfigSynchronization(&htim5, &sMasterConfig) != HAL_OK)
  {
    Error_Handler();
  }

}

static void MX_TIM6_Init(void)
{

  TIM_MasterConfigTypeDef sMasterConfig = {0};

  htim6.Instance = TIM6;
  htim6.Init.Prescaler = 11999;
  htim6.Init.CounterMode = TIM_COUNTERMODE_UP;
  htim6.Init.Period = 199;
  htim6.Init.AutoReloadPreload = TIM_AUTORELOAD_PRELOAD_DISABLE;
  if (HAL_TIM_Base_Init(&htim6) != HAL_OK)
  {
    Error_Handler();
  }
  sMasterConfig.MasterOutputTrigger = TIM_TRGO_UPDATE;
  sMasterConfig.MasterSlaveMode = TIM_MASTERSLAVEMODE_DISABLE;
  if (HAL_TIMEx_MasterConfigSynchronization(&htim6, &sMasterConfig) != HAL_OK)
  {
    Error_Handler();
  }

}

static void MX_TIM7_Init(void)
{

  TIM_MasterConfigTypeDef sMasterConfig = {0};

  htim7.Instance = TIM7;
  htim7.Init.Prescaler = 1199;
  htim7.Init.CounterMode = TIM_COUNTERMODE_UP;
  htim7.Init.Period = 199;
  htim7.Init.AutoReloadPreload = TIM_AUTORELOAD_PRELOAD_DISABLE;
  if (HAL_TIM_Base_Init(&htim7) != HAL_OK)
  {
    Error_Handler();
  }
  sMasterConfig.MasterOutputTrigger = TIM_TRGO_UPDATE;
  sMasterConfig.MasterSlaveMode = TIM_MASTERSLAVEMODE_DISABLE;
  if (HAL_TIMEx_MasterConfigSynchronization(&htim7, &sMasterConfig) != HAL_OK)
  {
    Error_Handler();
  }

}

static void MX_TIM15_Init(void)
{

  TIM_ClockConfigTypeDef sClockSourceConfig = {0};
  TIM_MasterConfigTypeDef sMasterConfig = {0};

  htim15.Instance = TIM15;
  htim15.Init.Prescaler = 1199;
  htim15.Init.CounterMode = TIM_COUNTERMODE_UP;
  htim15.Init.Period = 199;
  htim15.Init.ClockDivision = TIM_CLOCKDIVISION_DIV1;
  htim15.Init.RepetitionCounter = 0;
  htim15.Init.AutoReloadPreload = TIM_AUTORELOAD_PRELOAD_DISABLE;
  if (HAL_TIM_Base_Init(&htim15) != HAL_OK)
  {
    Error_Handler();
  }
  sClockSourceConfig.ClockSource = TIM_CLOCKSOURCE_INTERNAL;
  if (HAL_TIM_ConfigClockSource(&htim15, &sClockSourceConfig) != HAL_OK)
  {
    Error_Handler();
  }
  sMasterConfig.MasterOutputTrigger = TIM_TRGO_UPDATE;
  sMasterConfig.MasterSlaveMode = TIM_MASTERSLAVEMODE_DISABLE;
  if (HAL_TIMEx_MasterConfigSynchronization(&htim15, &sMasterConfig) != HAL_OK)
  {
    Error_Handler();
  }

}

static void MX_TIM16_Init(void)
{

  htim16.Instance = TIM16;
  htim16.Init.Prescaler = 1199;
  htim16.Init.CounterMode = TIM_COUNTERMODE_UP;
  htim16.Init.Period = 199;
  htim16.Init.ClockDivision = TIM_CLOCKDIVISION_DIV1;
  htim16.Init.RepetitionCounter = 0;
  htim16.Init.AutoReloadPreload = TIM_AUTORELOAD_PRELOAD_DISABLE;
  if (HAL_TIM_Base_Init(&htim16) != HAL_OK)
  {
    Error_Handler();
  }

}

static void MX_TIM17_Init(void)
{

  htim17.Instance = TIM17;
  htim17.Init.Prescaler = 119;
  htim17.Init.CounterMode = TIM_COUNTERMODE_UP;
  htim17.Init.Period = 99;
  htim17.Init.ClockDivision = TIM_CLOCKDIVISION_DIV1;
  htim17.Init.RepetitionCounter = 0;
  htim17.Init.AutoReloadPreload = TIM_AUTORELOAD_PRELOAD_DISABLE;
  if (HAL_TIM_Base_Init(&htim17) != HAL_OK)
  {
    Error_Handler();
  }

}

static void MX_USART6_UART_Init(void)
{

  huart6.Instance = USART6;
  huart6.Init.BaudRate = 115200;
  huart6.Init.WordLength = UART_WORDLENGTH_8B;
  huart6.Init.StopBits = UART_STOPBITS_1;
  huart6.Init.Parity = UART_PARITY_NONE;
  huart6.Init.Mode = UART_MODE_TX_RX;
  huart6.Init.HwFlowCtl = UART_HWCONTROL_NONE;
  huart6.Init.OverSampling = UART_OVERSAMPLING_16;
  huart6.Init.OneBitSampling = UART_ONE_BIT_SAMPLE_DISABLE;
  huart6.Init.ClockPrescaler = UART_PRESCALER_DIV1;
  huart6.AdvancedInit.AdvFeatureInit = UART_ADVFEATURE_NO_INIT;
  if (HAL_UART_Init(&huart6) != HAL_OK)
  {
    Error_Handler();
  }
  if (HAL_UARTEx_SetTxFifoThreshold(&huart6, UART_TXFIFO_THRESHOLD_1_8) != HAL_OK)
  {
    Error_Handler();
  }
  if (HAL_UARTEx_SetRxFifoThreshold(&huart6, UART_RXFIFO_THRESHOLD_1_8) != HAL_OK)
  {
    Error_Handler();
  }
  if (HAL_UARTEx_DisableFifoMode(&huart6) != HAL_OK)
  {
    Error_Handler();
  }

}

static void MX_USB_OTG_FS_PCD_Init(void)
{

  hpcd_USB_OTG_FS.Instance = USB_OTG_FS;
  hpcd_USB_OTG_FS.Init.dev_endpoints = 9;
  hpcd_USB_OTG_FS.Init.speed = PCD_SPEED_FULL;
  hpcd_USB_OTG_FS.Init.dma_enable = DISABLE;
  hpcd_USB_OTG_FS.Init.phy_itface = PCD_PHY_EMBEDDED;
  hpcd_USB_OTG_FS.Init.Sof_enable = ENABLE;
  hpcd_USB_OTG_FS.Init.low_power_enable = DISABLE;
  hpcd_USB_OTG_FS.Init.lpm_enable = DISABLE;
  hpcd_USB_OTG_FS.Init.battery_charging_enable = DISABLE;
  hpcd_USB_OTG_FS.Init.vbus_sensing_enable = DISABLE;
  hpcd_USB_OTG_FS.Init.use_dedicated_ep1 = DISABLE;
  if (HAL_PCD_Init(&hpcd_USB_OTG_FS) != HAL_OK)
  {
    Error_Handler();
  }

}

static void MX_DMA_Init(void)
{

  /* DMA controller clock enable */
  __HAL_RCC_DMA1_CLK_ENABLE();
  __HAL_RCC_DMA2_CLK_ENABLE();

  /* DMA interrupt init */
  /* DMA1_Stream1_IRQn interrupt configuration */
  HAL_NVIC_SetPriority(DMA1_Stream1_IRQn, 1, 0);
  HAL_NVIC_EnableIRQ(DMA1_Stream1_IRQn);
  /* DMA1_Stream2_IRQn interrupt configuration */
  HAL_NVIC_SetPriority(DMA1_Stream2_IRQn, 0, 0);
  HAL_NVIC_EnableIRQ(DMA1_Stream2_IRQn);
  /* DMA1_Stream3_IRQn interrupt configuration */
  HAL_NVIC_SetPriority(DMA1_Stream3_IRQn, 0, 0);
  HAL_NVIC_EnableIRQ(DMA1_Stream3_IRQn);
  /* DMA2_Stream5_IRQn interrupt configuration */
  HAL_NVIC_SetPriority(DMA2_Stream5_IRQn, 0, 0);
  HAL_NVIC_EnableIRQ(DMA2_Stream5_IRQn);

}

/**
  * Enable MDMA controller clock
  * Configure MDMA for global transfers
  *   hmdma_mdma_channel40_sw_0
  *   hmdma_mdma_channel41_sw_0
  *   hmdma_mdma_channel42_sw_0
  *   hmdma_mdma_channel43_sw_0
  *   hmdma_mdma_channel44_sw_0
  */
static void MX_MDMA_Init(void)
{

  /* MDMA controller clock enable */
  __HAL_RCC_MDMA_CLK_ENABLE();
  /* Local variables */

  /* Configure MDMA channel MDMA_Channel0 */
  /* Configure MDMA request hmdma_mdma_channel40_sw_0 on MDMA_Channel0 */
  hmdma_mdma_channel40_sw_0.Instance = MDMA_Channel0;
  hmdma_mdma_channel40_sw_0.Init.Request = MDMA_REQUEST_SW;
  hmdma_mdma_channel40_sw_0.Init.TransferTriggerMode = MDMA_FULL_TRANSFER;
  hmdma_mdma_channel40_sw_0.Init.Priority = MDMA_PRIORITY_MEDIUM;
  hmdma_mdma_channel40_sw_0.Init.Endianness = MDMA_LITTLE_ENDIANNESS_PRESERVE;
  hmdma_mdma_channel40_sw_0.Init.SourceInc = MDMA_SRC_INC_WORD;
  hmdma_mdma_channel40_sw_0.Init.DestinationInc = MDMA_DEST_INC_WORD;
  hmdma_mdma_channel40_sw_0.Init.SourceDataSize = MDMA_SRC_DATASIZE_WORD;
  hmdma_mdma_channel40_sw_0.Init.DestDataSize = MDMA_DEST_DATASIZE_WORD;
  hmdma_mdma_channel40_sw_0.Init.DataAlignment = MDMA_DATAALIGN_PACKENABLE;
  hmdma_mdma_channel40_sw_0.Init.BufferTransferLength = 32;
  hmdma_mdma_channel40_sw_0.Init.SourceBurst = MDMA_SOURCE_BURST_SINGLE;
  hmdma_mdma_channel40_sw_0.Init.DestBurst = MDMA_DEST_BURST_SINGLE;
  hmdma_mdma_channel40_sw_0.Init.SourceBlockAddressOffset = 0;
  hmdma_mdma_channel40_sw_0.Init.DestBlockAddressOffset = 0;
  if (HAL_MDMA_Init(&hmdma_mdma_channel40_sw_0) != HAL_OK)
  {
    Error_Handler();
  }

  /* Configure MDMA channel MDMA_Channel1 */
  /* Configure MDMA request hmdma_mdma_channel41_sw_0 on MDMA_Channel1 */
  hmdma_mdma_channel41_sw_0.Instance = MDMA_Channel1;
  hmdma_mdma_channel41_sw_0.Init.Request = MDMA_REQUEST_SW;
  hmdma_mdma_channel41_sw_0.Init.TransferTriggerMode = MDMA_FULL_TRANSFER;
  hmdma_mdma_channel41_sw_0.Init.Priority = MDMA_PRIORITY_MEDIUM;
  hmdma_mdma_channel41_sw_0.Init.Endianness = MDMA_LITTLE_ENDIANNESS_PRESERVE;
  hmdma_mdma_channel41_sw_0.Init.SourceInc = MDMA_SRC_INC_WORD;
  hmdma_mdma_channel41_sw_0.Init.DestinationInc = MDMA_DEST_INC_WORD;
  hmdma_mdma_channel41_sw_0.Init.SourceDataSize = MDMA_SRC_DATASIZE_WORD;
  hmdma_mdma_channel41_sw_0.Init.DestDataSize = MDMA_DEST_DATASIZE_WORD;
  hmdma_mdma_channel41_sw_0.Init.DataAlignment = MDMA_DATAALIGN_PACKENABLE;
  hmdma_mdma_channel41_sw_0.Init.BufferTransferLength = 32;
  hmdma_mdma_channel41_sw_0.Init.SourceBurst = MDMA_SOURCE_BURST_SINGLE;
  hmdma_mdma_channel41_sw_0.Init.DestBurst = MDMA_DEST_BURST_SINGLE;
  hmdma_mdma_channel41_sw_0.Init.SourceBlockAddressOffset = 0;
  hmdma_mdma_channel41_sw_0.Init.DestBlockAddressOffset = 0;
  if (HAL_MDMA_Init(&hmdma_mdma_channel41_sw_0) != HAL_OK)
  {
    Error_Handler();
  }

  /* Configure MDMA channel MDMA_Channel2 */
  /* Configure MDMA request hmdma_mdma_channel42_sw_0 on MDMA_Channel2 */
  hmdma_mdma_channel42_sw_0.Instance = MDMA_Channel2;
  hmdma_mdma_channel42_sw_0.Init.Request = MDMA_REQUEST_SW;
  hmdma_mdma_channel42_sw_0.Init.TransferTriggerMode = MDMA_FULL_TRANSFER;
  hmdma_mdma_channel42_sw_0.Init.Priority = MDMA_PRIORITY_MEDIUM;
  hmdma_mdma_channel42_sw_0.Init.Endianness = MDMA_LITTLE_ENDIANNESS_PRESERVE;
  hmdma_mdma_channel42_sw_0.Init.SourceInc = MDMA_SRC_INC_WORD;
  hmdma_mdma_channel42_sw_0.Init.DestinationInc = MDMA_DEST_INC_WORD;
  hmdma_mdma_channel42_sw_0.Init.SourceDataSize = MDMA_SRC_DATASIZE_WORD;
  hmdma_mdma_channel42_sw_0.Init.DestDataSize = MDMA_DEST_DATASIZE_WORD;
  hmdma_mdma_channel42_sw_0.Init.DataAlignment = MDMA_DATAALIGN_PACKENABLE;
  hmdma_mdma_channel42_sw_0.Init.BufferTransferLength = 32;
  hmdma_mdma_channel42_sw_0.Init.SourceBurst = MDMA_SOURCE_BURST_SINGLE;
  hmdma_mdma_channel42_sw_0.Init.DestBurst = MDMA_DEST_BURST_SINGLE;
  hmdma_mdma_channel42_sw_0.Init.SourceBlockAddressOffset = 0;
  hmdma_mdma_channel42_sw_0.Init.DestBlockAddressOffset = 0;
  if (HAL_MDMA_Init(&hmdma_mdma_channel42_sw_0) != HAL_OK)
  {
    Error_Handler();
  }

  /* Configure MDMA channel MDMA_Channel3 */
  /* Configure MDMA request hmdma_mdma_channel43_sw_0 on MDMA_Channel3 */
  hmdma_mdma_channel43_sw_0.Instance = MDMA_Channel3;
  hmdma_mdma_channel43_sw_0.Init.Request = MDMA_REQUEST_SW;
  hmdma_mdma_channel43_sw_0.Init.TransferTriggerMode = MDMA_FULL_TRANSFER;
  hmdma_mdma_channel43_sw_0.Init.Priority = MDMA_PRIORITY_LOW;
  hmdma_mdma_channel43_sw_0.Init.Endianness = MDMA_LITTLE_ENDIANNESS_PRESERVE;
  hmdma_mdma_channel43_sw_0.Init.SourceInc = MDMA_SRC_DEC_BYTE;
  hmdma_mdma_channel43_sw_0.Init.DestinationInc = MDMA_DEST_DEC_BYTE;
  hmdma_mdma_channel43_sw_0.Init.SourceDataSize = MDMA_SRC_DATASIZE_BYTE;
  hmdma_mdma_channel43_sw_0.Init.DestDataSize = MDMA_DEST_DATASIZE_BYTE;
  hmdma_mdma_channel43_sw_0.Init.DataAlignment = MDMA_DATAALIGN_PACKENABLE;
  hmdma_mdma_channel43_sw_0.Init.BufferTransferLength = 32;
  hmdma_mdma_channel43_sw_0.Init.SourceBurst = MDMA_SOURCE_BURST_SINGLE;
  hmdma_mdma_channel43_sw_0.Init.DestBurst = MDMA_DEST_BURST_SINGLE;
  hmdma_mdma_channel43_sw_0.Init.SourceBlockAddressOffset = 0;
  hmdma_mdma_channel43_sw_0.Init.DestBlockAddressOffset = 0;
  if (HAL_MDMA_Init(&hmdma_mdma_channel43_sw_0) != HAL_OK)
  {
    Error_Handler();
  }

  /* Configure MDMA channel MDMA_Channel4 */
  /* Configure MDMA request hmdma_mdma_channel44_sw_0 on MDMA_Channel4 */
  hmdma_mdma_channel44_sw_0.Instance = MDMA_Channel4;
  hmdma_mdma_channel44_sw_0.Init.Request = MDMA_REQUEST_SW;
  hmdma_mdma_channel44_sw_0.Init.TransferTriggerMode = MDMA_FULL_TRANSFER;
  hmdma_mdma_channel44_sw_0.Init.Priority = MDMA_PRIORITY_MEDIUM;
  hmdma_mdma_channel44_sw_0.Init.Endianness = MDMA_LITTLE_ENDIANNESS_PRESERVE;
  hmdma_mdma_channel44_sw_0.Init.SourceInc = MDMA_SRC_INC_DISABLE;
  hmdma_mdma_channel44_sw_0.Init.DestinationInc = MDMA_DEST_INC_WORD;
  hmdma_mdma_channel44_sw_0.Init.SourceDataSize = MDMA_SRC_DATASIZE_WORD;
  hmdma_mdma_channel44_sw_0.Init.DestDataSize = MDMA_DEST_DATASIZE_WORD;
  hmdma_mdma_channel44_sw_0.Init.DataAlignment = MDMA_DATAALIGN_PACKENABLE;
  hmdma_mdma_channel44_sw_0.Init.BufferTransferLength = 32;
  hmdma_mdma_channel44_sw_0.Init.SourceBurst = MDMA_SOURCE_BURST_SINGLE;
  hmdma_mdma_channel44_sw_0.Init.DestBurst = MDMA_DEST_BURST_SINGLE;
  hmdma_mdma_channel44_sw_0.Init.SourceBlockAddressOffset = 0;
  hmdma_mdma_channel44_sw_0.Init.DestBlockAddressOffset = 0;
  if (HAL_MDMA_Init(&hmdma_mdma_channel44_sw_0) != HAL_OK)
  {
    Error_Handler();
  }

}

static void MX_GPIO_Init(void)
{
  GPIO_InitTypeDef GPIO_InitStruct = {0};

  /* GPIO Ports Clock Enable */
  __HAL_RCC_GPIOE_CLK_ENABLE();
  __HAL_RCC_GPIOC_CLK_ENABLE();
  __HAL_RCC_GPIOH_CLK_ENABLE();
  __HAL_RCC_GPIOA_CLK_ENABLE();
  __HAL_RCC_GPIOB_CLK_ENABLE();
  __HAL_RCC_GPIOD_CLK_ENABLE();

  /*Configure GPIO pin Output Level */
  HAL_GPIO_WritePin(GPIOC, FPGA_CLK_Pin|FPGA_SYNC_Pin, GPIO_PIN_RESET);

  /*Configure GPIO pin Output Level */
  HAL_GPIO_WritePin(GPIOA, FPGA_BUS_D0_Pin|FPGA_BUS_D1_Pin|FPGA_BUS_D2_Pin|FPGA_BUS_D3_Pin
                          |FPGA_BUS_D4_Pin|FPGA_BUS_D5_Pin|FPGA_BUS_D6_Pin|FPGA_BUS_D7_Pin, GPIO_PIN_RESET);

  /*Configure GPIO pin Output Level */
  HAL_GPIO_WritePin(GPIOB, W25Q16_CS_Pin|SD_CS_Pin|RFUNIT_OE_Pin, GPIO_PIN_SET);

  /*Configure GPIO pin Output Level */
  HAL_GPIO_WritePin(GPIOE, LCD_RST_Pin|LCD_DC_Pin, GPIO_PIN_RESET);

  /*Configure GPIO pin Output Level */
  HAL_GPIO_WritePin(PWR_HOLD_GPIO_Port, PWR_HOLD_Pin, GPIO_PIN_SET);

  /*Configure GPIO pin Output Level */
  HAL_GPIO_WritePin(GPIOD, ATT_ON_16_Pin|ATT_ON_0_5_Pin|ATT_ON_1_Pin|WM8731_SCK_Pin
                          |WM8731_SDA_Pin, GPIO_PIN_RESET);

  /*Configure GPIO pin Output Level */
  HAL_GPIO_WritePin(GPIOB, RFUNIT_RCLK_Pin|RFUNIT_CLK_Pin|RFUNIT_DATA_Pin, GPIO_PIN_RESET);

  /*Configure GPIO pins : ENC_CLK_Pin PTT_IN_Pin KEY_IN_DASH_Pin KEY_IN_DOT_Pin */
  GPIO_InitStruct.Pin = ENC_CLK_Pin|PTT_IN_Pin|KEY_IN_DASH_Pin|KEY_IN_DOT_Pin;
  GPIO_InitStruct.Mode = GPIO_MODE_IT_RISING_FALLING;
  GPIO_InitStruct.Pull = GPIO_PULLUP;
  HAL_GPIO_Init(GPIOE, &GPIO_InitStruct);

  /*Configure GPIO pins : PE3 PE4 PE6 */
  GPIO_InitStruct.Pin = GPIO_PIN_3|GPIO_PIN_4|GPIO_PIN_6;
  GPIO_InitStruct.Mode = GPIO_MODE_ANALOG;
  GPIO_InitStruct.Pull = GPIO_NOPULL;
  HAL_GPIO_Init(GPIOE, &GPIO_InitStruct);

  /*Configure GPIO pins : ENC_DT_Pin KEY_4_Pin KEY_3_Pin */
  GPIO_InitStruct.Pin = ENC_DT_Pin|KEY_4_Pin|KEY_3_Pin;
  GPIO_InitStruct.Mode = GPIO_MODE_INPUT;
  GPIO_InitStruct.Pull = GPIO_PULLUP;
  HAL_GPIO_Init(GPIOE, &GPIO_InitStruct);

  /*Configure GPIO pin : KEY_6_Pin */
  GPIO_InitStruct.Pin = KEY_6_Pin;
  GPIO_InitStruct.Mode = GPIO_MODE_INPUT;
  GPIO_InitStruct.Pull = GPIO_PULLUP;
  HAL_GPIO_Init(KEY_6_GPIO_Port, &GPIO_InitStruct);

  /*Configure GPIO pins : FPGA_CLK_Pin FPGA_SYNC_Pin */
  GPIO_InitStruct.Pin = FPGA_CLK_Pin|FPGA_SYNC_Pin;
  GPIO_InitStruct.Mode = GPIO_MODE_OUTPUT_PP;
  GPIO_InitStruct.Pull = GPIO_PULLUP;
  GPIO_InitStruct.Speed = GPIO_SPEED_FREQ_LOW;
  HAL_GPIO_Init(GPIOC, &GPIO_InitStruct);

  /*Configure GPIO pins : FPGA_BUS_D0_Pin FPGA_BUS_D1_Pin FPGA_BUS_D2_Pin FPGA_BUS_D3_Pin
                           FPGA_BUS_D4_Pin FPGA_BUS_D5_Pin FPGA_BUS_D6_Pin FPGA_BUS_D7_Pin */
  GPIO_InitStruct.Pin = FPGA_BUS_D0_Pin|FPGA_BUS_D1_Pin|FPGA_BUS_D2_Pin|FPGA_BUS_D3_Pin
                          |FPGA_BUS_D4_Pin|FPGA_BUS_D5_Pin|FPGA_BUS_D6_Pin|FPGA_BUS_D7_Pin;
  GPIO_InitStruct.Mode = GPIO_MODE_OUTPUT_PP;
  GPIO_InitStruct.Pull = GPIO_PULLUP;
  GPIO_InitStruct.Speed = GPIO_SPEED_FREQ_LOW;
  HAL_GPIO_Init(GPIOA, &GPIO_InitStruct);

  /*Configure GPIO pins : PC4 PC8 */
  GPIO_InitStruct.Pin = GPIO_PIN_4|GPIO_PIN_8;
  GPIO_InitStruct.Mode = GPIO_MODE_ANALOG;
  GPIO_InitStruct.Pull = GPIO_NOPULL;
  HAL_GPIO_Init(GPIOC, &GPIO_InitStruct);

  /*Configure GPIO pins : W25Q16_CS_Pin SD_CS_Pin RFUNIT_RCLK_Pin RFUNIT_CLK_Pin
                           RFUNIT_DATA_Pin RFUNIT_OE_Pin */
  GPIO_InitStruct.Pin = W25Q16_CS_Pin|SD_CS_Pin|RFUNIT_RCLK_Pin|RFUNIT_CLK_Pin
                          |RFUNIT_DATA_Pin|RFUNIT_OE_Pin;
  GPIO_InitStruct.Mode = GPIO_MODE_OUTPUT_PP;
  GPIO_InitStruct.Pull = GPIO_PULLUP;
  GPIO_InitStruct.Speed = GPIO_SPEED_FREQ_LOW;
  HAL_GPIO_Init(GPIOB, &GPIO_InitStruct);

  /*Configure GPIO pins : LCD_RST_Pin LCD_DC_Pin */
  GPIO_InitStruct.Pin = LCD_RST_Pin|LCD_DC_Pin;
  GPIO_InitStruct.Mode = GPIO_MODE_OUTPUT_PP;
  GPIO_InitStruct.Pull = GPIO_NOPULL;
  GPIO_InitStruct.Speed = GPIO_SPEED_FREQ_LOW;
  HAL_GPIO_Init(GPIOE, &GPIO_InitStruct);

  /*Configure GPIO pin : AUDIO_48K_CLOCK_Pin */
  GPIO_InitStruct.Pin = AUDIO_48K_CLOCK_Pin;
  GPIO_InitStruct.Mode = GPIO_MODE_IT_RISING;
  GPIO_InitStruct.Pull = GPIO_PULLUP;
  HAL_GPIO_Init(AUDIO_48K_CLOCK_GPIO_Port, &GPIO_InitStruct);

  /*Configure GPIO pins : PB12 PB4 */
  GPIO_InitStruct.Pin = GPIO_PIN_12|GPIO_PIN_4;
  GPIO_InitStruct.Mode = GPIO_MODE_ANALOG;
  GPIO_InitStruct.Pull = GPIO_NOPULL;
  HAL_GPIO_Init(GPIOB, &GPIO_InitStruct);

  /*Configure GPIO pins : PD8 PD13 PD14 PD15
                           PD5 */
  GPIO_InitStruct.Pin = GPIO_PIN_8|GPIO_PIN_13|GPIO_PIN_14|GPIO_PIN_15
                          |GPIO_PIN_5;
  GPIO_InitStruct.Mode = GPIO_MODE_ANALOG;
  GPIO_InitStruct.Pull = GPIO_NOPULL;
  HAL_GPIO_Init(GPIOD, &GPIO_InitStruct);

  /*Configure GPIO pins : KEY_2_Pin KEY_1_Pin KEY_5_Pin ENC2_SW_Pin */
  GPIO_InitStruct.Pin = KEY_2_Pin|KEY_1_Pin|KEY_5_Pin|ENC2_SW_Pin;
  GPIO_InitStruct.Mode = GPIO_MODE_INPUT;
  GPIO_InitStruct.Pull = GPIO_PULLUP;
  HAL_GPIO_Init(GPIOD, &GPIO_InitStruct);

  /*Configure GPIO pin : PWR_ON_Pin */
  GPIO_InitStruct.Pin = PWR_ON_Pin;
  GPIO_InitStruct.Mode = GPIO_MODE_IT_FALLING;
  GPIO_InitStruct.Pull = GPIO_PULLUP;
  HAL_GPIO_Init(PWR_ON_GPIO_Port, &GPIO_InitStruct);

  /*Configure GPIO pins : PWR_HOLD_Pin WM8731_SCK_Pin WM8731_SDA_Pin */
  GPIO_InitStruct.Pin = PWR_HOLD_Pin|WM8731_SCK_Pin|WM8731_SDA_Pin;
  GPIO_InitStruct.Mode = GPIO_MODE_OUTPUT_PP;
  GPIO_InitStruct.Pull = GPIO_PULLUP;
  GPIO_InitStruct.Speed = GPIO_SPEED_FREQ_LOW;
  HAL_GPIO_Init(GPIOD, &GPIO_InitStruct);

  /*Configure GPIO pin : AUDIO_I2S_CLOCK_Pin */
  GPIO_InitStruct.Pin = AUDIO_I2S_CLOCK_Pin;
  GPIO_InitStruct.Mode = GPIO_MODE_AF_PP;
  GPIO_InitStruct.Pull = GPIO_PULLDOWN;
  GPIO_InitStruct.Speed = GPIO_SPEED_FREQ_LOW;
  GPIO_InitStruct.Alternate = GPIO_AF5_SPI1;
  HAL_GPIO_Init(AUDIO_I2S_CLOCK_GPIO_Port, &GPIO_InitStruct);

  /*Configure GPIO pin : PA8 */
  GPIO_InitStruct.Pin = GPIO_PIN_8;
  GPIO_InitStruct.Mode = GPIO_MODE_ANALOG;
  GPIO_InitStruct.Pull = GPIO_NOPULL;
  HAL_GPIO_Init(GPIOA, &GPIO_InitStruct);

  /*Configure GPIO pins : ENC2_DT_Pin ENC2_CLK_Pin */
  GPIO_InitStruct.Pin = ENC2_DT_Pin|ENC2_CLK_Pin;
  GPIO_InitStruct.Mode = GPIO_MODE_INPUT;
  GPIO_InitStruct.Pull = GPIO_PULLUP;
  HAL_GPIO_Init(GPIOA, &GPIO_InitStruct);

  /*Configure GPIO pins : ATT_ON_16_Pin ATT_ON_0_5_Pin ATT_ON_1_Pin */
  GPIO_InitStruct.Pin = ATT_ON_16_Pin|ATT_ON_0_5_Pin|ATT_ON_1_Pin;
  GPIO_InitStruct.Mode = GPIO_MODE_OUTPUT_PP;
  GPIO_InitStruct.Pull = GPIO_PULLDOWN;
  GPIO_InitStruct.Speed = GPIO_SPEED_FREQ_LOW;
  HAL_GPIO_Init(GPIOD, &GPIO_InitStruct);

  /*Configure GPIO pin : KEY_7_Pin */
  GPIO_InitStruct.Pin = KEY_7_Pin;
  GPIO_InitStruct.Mode = GPIO_MODE_INPUT;
  GPIO_InitStruct.Pull = GPIO_PULLUP;
  HAL_GPIO_Init(KEY_7_GPIO_Port, &GPIO_InitStruct);

  /* EXTI interrupt init*/
  HAL_NVIC_SetPriority(EXTI0_IRQn, 6, 0);
  HAL_NVIC_EnableIRQ(EXTI0_IRQn);

  HAL_NVIC_SetPriority(EXTI1_IRQn, 6, 0);
  HAL_NVIC_EnableIRQ(EXTI1_IRQn);

  HAL_NVIC_SetPriority(EXTI2_IRQn, 2, 0);
  HAL_NVIC_EnableIRQ(EXTI2_IRQn);

  HAL_NVIC_SetPriority(EXTI9_5_IRQn, 6, 0);
  HAL_NVIC_EnableIRQ(EXTI9_5_IRQn);

  HAL_NVIC_SetPriority(EXTI15_10_IRQn, 3, 0);
  HAL_NVIC_EnableIRQ(EXTI15_10_IRQn);

}

/* USER CODE BEGIN 4 */
//обработка вывода отладки
FILE __stdout;
FILE __stdin;

int fputc(int ch, FILE *f)
{
#pragma unused(f)

  //SWD
  if (SWD_DEBUG_ENABLED)
    ITM_SendChar((uint32_t)ch);

  //USB
  if (USB_DEBUG_ENABLED)
  {
    char usb_char = (char)ch;
    DEBUG_Transmit_FIFO((uint8_t *)&usb_char, 1);
  }

  //LCD
  if (LCD_DEBUG_ENABLED)
  {
    print_chr_LCDOnly((char)ch);
  }

  return (ch);
}
/* USER CODE END 4 */

/* MPU Configuration */

void MPU_Config(void)
{
  MPU_Region_InitTypeDef MPU_InitStruct = {0};

  /* Disables the MPU */
  HAL_MPU_Disable();

  /** Initializes and configures the Region and the memory to be protected
  */
  MPU_InitStruct.Enable = MPU_REGION_ENABLE;
  MPU_InitStruct.Number = MPU_REGION_NUMBER0;
  MPU_InitStruct.BaseAddress = 0x60000000;
  MPU_InitStruct.Size = MPU_REGION_SIZE_1MB;
  MPU_InitStruct.SubRegionDisable = 0x0;
  MPU_InitStruct.TypeExtField = MPU_TEX_LEVEL0;
  MPU_InitStruct.AccessPermission = MPU_REGION_FULL_ACCESS;
  MPU_InitStruct.DisableExec = MPU_INSTRUCTION_ACCESS_ENABLE;
  MPU_InitStruct.IsShareable = MPU_ACCESS_SHAREABLE;
  MPU_InitStruct.IsCacheable = MPU_ACCESS_NOT_CACHEABLE;
  MPU_InitStruct.IsBufferable = MPU_ACCESS_NOT_BUFFERABLE;

  HAL_MPU_ConfigRegion(&MPU_InitStruct);

  /** Initializes and configures the Region and the memory to be protected
  */
  MPU_InitStruct.Number = MPU_REGION_NUMBER2;
  MPU_InitStruct.BaseAddress = 0x38800000;
  MPU_InitStruct.Size = MPU_REGION_SIZE_4KB;

  HAL_MPU_ConfigRegion(&MPU_InitStruct);
  /* Enables the MPU */
  HAL_MPU_Enable(MPU_PRIVILEGED_DEFAULT);

}

void Error_Handler(void)
{
  /* USER CODE BEGIN Error_Handler_Debug */
  /* User can add his own implementation to report the HAL error return state */
  println("error handled");
  /*while (1)
	{
		LCD_showError("Error handled", true);
	}*/
  //LCD_showError("Error handled", true);
  /* USER CODE END Error_Handler_Debug */
}

#ifdef  USE_FULL_ASSERT
/**
  * @brief  Reports the name of the source file and the source line number
  *         where the assert_param error has occurred.
  * @param  file: pointer to the source file name
  * @param  line: assert_param error line source number
  * @retval None
  */
void assert_failed(uint8_t *file, uint32_t line)
{
  /* USER CODE BEGIN 6 */
  /* User can add his own implementation to report the file name and line number,
     tex: printf("Wrong parameters value: file %s on line %d\r\n", file, line) */
  printf("Wrong parameters value: file %s on line %u\r\n", file, line);
  /* USER CODE END 6 */
}
#endif /* USE_FULL_ASSERT */
